# Generated by FakeRAM 2.0
VERSION 5.7 ;
BUSBITCHARS "[]" ;
PROPERTYDEFINITIONS
  MACRO width INTEGER ;
  MACRO depth INTEGER ;
  MACRO banks INTEGER ;
END PROPERTYDEFINITIONS
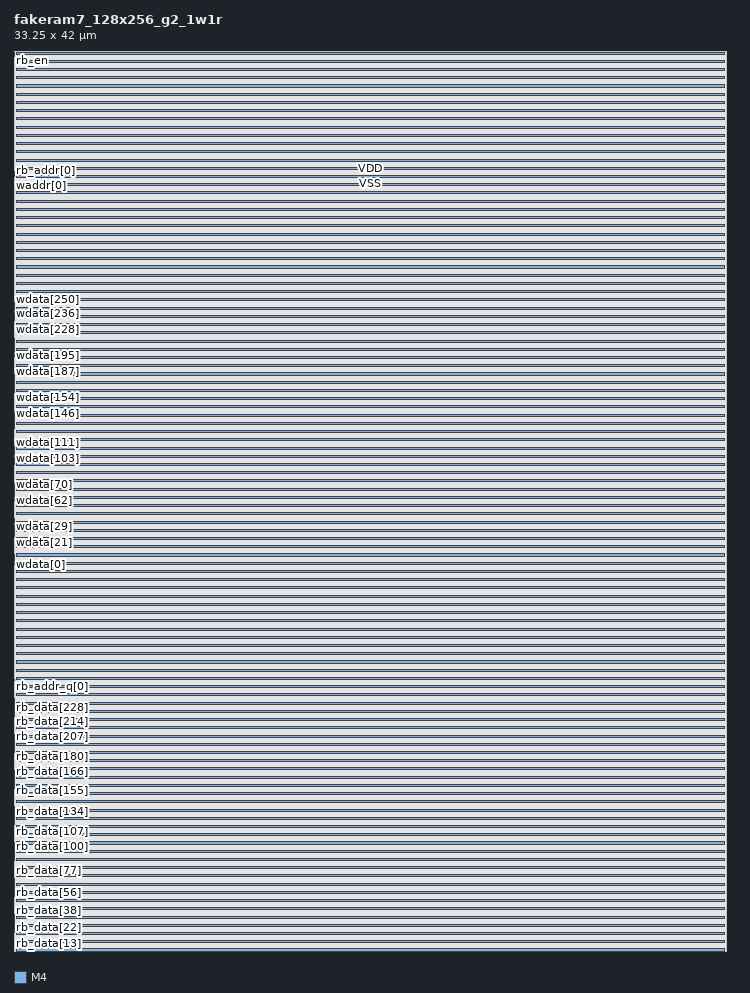
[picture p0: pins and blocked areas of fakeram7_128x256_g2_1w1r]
MACRO fakeram7_128x256_g2_1w1r
  PROPERTY width 256 ;
  PROPERTY depth 128 ;
  PROPERTY banks 1 ;
  FOREIGN fakeram7_128x256_g2_1w1r 0 0 ;
  SYMMETRY X Y R90 ;
  SIZE 33.2500 BY 42.0000 ;
  CLASS BLOCK ;
  PIN wdata[0]
    DIRECTION INPUT ;
    USE SIGNAL ;
    PORT
      LAYER M4 ;
      RECT 0.00000 18.04800 0.03600 18.07200 ;
    END
  END wdata[0]
  PIN wdata[1]
    DIRECTION INPUT ;
    USE SIGNAL ;
    PORT
      LAYER M4 ;
      RECT 0.00000 18.09600 0.03600 18.12000 ;
    END
  END wdata[1]
  PIN wdata[2]
    DIRECTION INPUT ;
    USE SIGNAL ;
    PORT
      LAYER M4 ;
      RECT 0.00000 18.14400 0.03600 18.16800 ;
    END
  END wdata[2]
  PIN wdata[3]
    DIRECTION INPUT ;
    USE SIGNAL ;
    PORT
      LAYER M4 ;
      RECT 0.00000 18.19200 0.03600 18.21600 ;
    END
  END wdata[3]
  PIN wdata[4]
    DIRECTION INPUT ;
    USE SIGNAL ;
    PORT
      LAYER M4 ;
      RECT 0.00000 18.24000 0.03600 18.26400 ;
    END
  END wdata[4]
  PIN wdata[5]
    DIRECTION INPUT ;
    USE SIGNAL ;
    PORT
      LAYER M4 ;
      RECT 0.00000 18.28800 0.03600 18.31200 ;
    END
  END wdata[5]
  PIN wdata[6]
    DIRECTION INPUT ;
    USE SIGNAL ;
    PORT
      LAYER M4 ;
      RECT 0.00000 18.33600 0.03600 18.36000 ;
    END
  END wdata[6]
  PIN wdata[7]
    DIRECTION INPUT ;
    USE SIGNAL ;
    PORT
      LAYER M4 ;
      RECT 0.00000 18.38400 0.03600 18.40800 ;
    END
  END wdata[7]
  PIN wdata[8]
    DIRECTION INPUT ;
    USE SIGNAL ;
    PORT
      LAYER M4 ;
      RECT 0.00000 18.43200 0.03600 18.45600 ;
    END
  END wdata[8]
  PIN wdata[9]
    DIRECTION INPUT ;
    USE SIGNAL ;
    PORT
      LAYER M4 ;
      RECT 0.00000 18.48000 0.03600 18.50400 ;
    END
  END wdata[9]
  PIN wdata[10]
    DIRECTION INPUT ;
    USE SIGNAL ;
    PORT
      LAYER M4 ;
      RECT 0.00000 18.52800 0.03600 18.55200 ;
    END
  END wdata[10]
  PIN wdata[11]
    DIRECTION INPUT ;
    USE SIGNAL ;
    PORT
      LAYER M4 ;
      RECT 0.00000 18.57600 0.03600 18.60000 ;
    END
  END wdata[11]
  PIN wdata[12]
    DIRECTION INPUT ;
    USE SIGNAL ;
    PORT
      LAYER M4 ;
      RECT 0.00000 18.62400 0.03600 18.64800 ;
    END
  END wdata[12]
  PIN wdata[13]
    DIRECTION INPUT ;
    USE SIGNAL ;
    PORT
      LAYER M4 ;
      RECT 0.00000 18.67200 0.03600 18.69600 ;
    END
  END wdata[13]
  PIN wdata[14]
    DIRECTION INPUT ;
    USE SIGNAL ;
    PORT
      LAYER M4 ;
      RECT 0.00000 18.72000 0.03600 18.74400 ;
    END
  END wdata[14]
  PIN wdata[15]
    DIRECTION INPUT ;
    USE SIGNAL ;
    PORT
      LAYER M4 ;
      RECT 0.00000 18.76800 0.03600 18.79200 ;
    END
  END wdata[15]
  PIN wdata[16]
    DIRECTION INPUT ;
    USE SIGNAL ;
    PORT
      LAYER M4 ;
      RECT 0.00000 18.81600 0.03600 18.84000 ;
    END
  END wdata[16]
  PIN wdata[17]
    DIRECTION INPUT ;
    USE SIGNAL ;
    PORT
      LAYER M4 ;
      RECT 0.00000 18.86400 0.03600 18.88800 ;
    END
  END wdata[17]
  PIN wdata[18]
    DIRECTION INPUT ;
    USE SIGNAL ;
    PORT
      LAYER M4 ;
      RECT 0.00000 18.91200 0.03600 18.93600 ;
    END
  END wdata[18]
  PIN wdata[19]
    DIRECTION INPUT ;
    USE SIGNAL ;
    PORT
      LAYER M4 ;
      RECT 0.00000 18.96000 0.03600 18.98400 ;
    END
  END wdata[19]
  PIN wdata[20]
    DIRECTION INPUT ;
    USE SIGNAL ;
    PORT
      LAYER M4 ;
      RECT 0.00000 19.00800 0.03600 19.03200 ;
    END
  END wdata[20]
  PIN wdata[21]
    DIRECTION INPUT ;
    USE SIGNAL ;
    PORT
      LAYER M4 ;
      RECT 0.00000 19.05600 0.03600 19.08000 ;
    END
  END wdata[21]
  PIN wdata[22]
    DIRECTION INPUT ;
    USE SIGNAL ;
    PORT
      LAYER M4 ;
      RECT 0.00000 19.10400 0.03600 19.12800 ;
    END
  END wdata[22]
  PIN wdata[23]
    DIRECTION INPUT ;
    USE SIGNAL ;
    PORT
      LAYER M4 ;
      RECT 0.00000 19.15200 0.03600 19.17600 ;
    END
  END wdata[23]
  PIN wdata[24]
    DIRECTION INPUT ;
    USE SIGNAL ;
    PORT
      LAYER M4 ;
      RECT 0.00000 19.20000 0.03600 19.22400 ;
    END
  END wdata[24]
  PIN wdata[25]
    DIRECTION INPUT ;
    USE SIGNAL ;
    PORT
      LAYER M4 ;
      RECT 0.00000 19.24800 0.03600 19.27200 ;
    END
  END wdata[25]
  PIN wdata[26]
    DIRECTION INPUT ;
    USE SIGNAL ;
    PORT
      LAYER M4 ;
      RECT 0.00000 19.29600 0.03600 19.32000 ;
    END
  END wdata[26]
  PIN wdata[27]
    DIRECTION INPUT ;
    USE SIGNAL ;
    PORT
      LAYER M4 ;
      RECT 0.00000 19.34400 0.03600 19.36800 ;
    END
  END wdata[27]
  PIN wdata[28]
    DIRECTION INPUT ;
    USE SIGNAL ;
    PORT
      LAYER M4 ;
      RECT 0.00000 19.39200 0.03600 19.41600 ;
    END
  END wdata[28]
  PIN wdata[29]
    DIRECTION INPUT ;
    USE SIGNAL ;
    PORT
      LAYER M4 ;
      RECT 0.00000 19.44000 0.03600 19.46400 ;
    END
  END wdata[29]
  PIN wdata[30]
    DIRECTION INPUT ;
    USE SIGNAL ;
    PORT
      LAYER M4 ;
      RECT 0.00000 19.48800 0.03600 19.51200 ;
    END
  END wdata[30]
  PIN wdata[31]
    DIRECTION INPUT ;
    USE SIGNAL ;
    PORT
      LAYER M4 ;
      RECT 0.00000 19.53600 0.03600 19.56000 ;
    END
  END wdata[31]
  PIN wdata[32]
    DIRECTION INPUT ;
    USE SIGNAL ;
    PORT
      LAYER M4 ;
      RECT 0.00000 19.58400 0.03600 19.60800 ;
    END
  END wdata[32]
  PIN wdata[33]
    DIRECTION INPUT ;
    USE SIGNAL ;
    PORT
      LAYER M4 ;
      RECT 0.00000 19.63200 0.03600 19.65600 ;
    END
  END wdata[33]
  PIN wdata[34]
    DIRECTION INPUT ;
    USE SIGNAL ;
    PORT
      LAYER M4 ;
      RECT 0.00000 19.68000 0.03600 19.70400 ;
    END
  END wdata[34]
  PIN wdata[35]
    DIRECTION INPUT ;
    USE SIGNAL ;
    PORT
      LAYER M4 ;
      RECT 0.00000 19.72800 0.03600 19.75200 ;
    END
  END wdata[35]
  PIN wdata[36]
    DIRECTION INPUT ;
    USE SIGNAL ;
    PORT
      LAYER M4 ;
      RECT 0.00000 19.77600 0.03600 19.80000 ;
    END
  END wdata[36]
  PIN wdata[37]
    DIRECTION INPUT ;
    USE SIGNAL ;
    PORT
      LAYER M4 ;
      RECT 0.00000 19.82400 0.03600 19.84800 ;
    END
  END wdata[37]
  PIN wdata[38]
    DIRECTION INPUT ;
    USE SIGNAL ;
    PORT
      LAYER M4 ;
      RECT 0.00000 19.87200 0.03600 19.89600 ;
    END
  END wdata[38]
  PIN wdata[39]
    DIRECTION INPUT ;
    USE SIGNAL ;
    PORT
      LAYER M4 ;
      RECT 0.00000 19.92000 0.03600 19.94400 ;
    END
  END wdata[39]
  PIN wdata[40]
    DIRECTION INPUT ;
    USE SIGNAL ;
    PORT
      LAYER M4 ;
      RECT 0.00000 19.96800 0.03600 19.99200 ;
    END
  END wdata[40]
  PIN wdata[41]
    DIRECTION INPUT ;
    USE SIGNAL ;
    PORT
      LAYER M4 ;
      RECT 0.00000 20.01600 0.03600 20.04000 ;
    END
  END wdata[41]
  PIN wdata[42]
    DIRECTION INPUT ;
    USE SIGNAL ;
    PORT
      LAYER M4 ;
      RECT 0.00000 20.06400 0.03600 20.08800 ;
    END
  END wdata[42]
  PIN wdata[43]
    DIRECTION INPUT ;
    USE SIGNAL ;
    PORT
      LAYER M4 ;
      RECT 0.00000 20.11200 0.03600 20.13600 ;
    END
  END wdata[43]
  PIN wdata[44]
    DIRECTION INPUT ;
    USE SIGNAL ;
    PORT
      LAYER M4 ;
      RECT 0.00000 20.16000 0.03600 20.18400 ;
    END
  END wdata[44]
  PIN wdata[45]
    DIRECTION INPUT ;
    USE SIGNAL ;
    PORT
      LAYER M4 ;
      RECT 0.00000 20.20800 0.03600 20.23200 ;
    END
  END wdata[45]
  PIN wdata[46]
    DIRECTION INPUT ;
    USE SIGNAL ;
    PORT
      LAYER M4 ;
      RECT 0.00000 20.25600 0.03600 20.28000 ;
    END
  END wdata[46]
  PIN wdata[47]
    DIRECTION INPUT ;
    USE SIGNAL ;
    PORT
      LAYER M4 ;
      RECT 0.00000 20.30400 0.03600 20.32800 ;
    END
  END wdata[47]
  PIN wdata[48]
    DIRECTION INPUT ;
    USE SIGNAL ;
    PORT
      LAYER M4 ;
      RECT 0.00000 20.35200 0.03600 20.37600 ;
    END
  END wdata[48]
  PIN wdata[49]
    DIRECTION INPUT ;
    USE SIGNAL ;
    PORT
      LAYER M4 ;
      RECT 0.00000 20.40000 0.03600 20.42400 ;
    END
  END wdata[49]
  PIN wdata[50]
    DIRECTION INPUT ;
    USE SIGNAL ;
    PORT
      LAYER M4 ;
      RECT 0.00000 20.44800 0.03600 20.47200 ;
    END
  END wdata[50]
  PIN wdata[51]
    DIRECTION INPUT ;
    USE SIGNAL ;
    PORT
      LAYER M4 ;
      RECT 0.00000 20.49600 0.03600 20.52000 ;
    END
  END wdata[51]
  PIN wdata[52]
    DIRECTION INPUT ;
    USE SIGNAL ;
    PORT
      LAYER M4 ;
      RECT 0.00000 20.54400 0.03600 20.56800 ;
    END
  END wdata[52]
  PIN wdata[53]
    DIRECTION INPUT ;
    USE SIGNAL ;
    PORT
      LAYER M4 ;
      RECT 0.00000 20.59200 0.03600 20.61600 ;
    END
  END wdata[53]
  PIN wdata[54]
    DIRECTION INPUT ;
    USE SIGNAL ;
    PORT
      LAYER M4 ;
      RECT 0.00000 20.64000 0.03600 20.66400 ;
    END
  END wdata[54]
  PIN wdata[55]
    DIRECTION INPUT ;
    USE SIGNAL ;
    PORT
      LAYER M4 ;
      RECT 0.00000 20.68800 0.03600 20.71200 ;
    END
  END wdata[55]
  PIN wdata[56]
    DIRECTION INPUT ;
    USE SIGNAL ;
    PORT
      LAYER M4 ;
      RECT 0.00000 20.73600 0.03600 20.76000 ;
    END
  END wdata[56]
  PIN wdata[57]
    DIRECTION INPUT ;
    USE SIGNAL ;
    PORT
      LAYER M4 ;
      RECT 0.00000 20.78400 0.03600 20.80800 ;
    END
  END wdata[57]
  PIN wdata[58]
    DIRECTION INPUT ;
    USE SIGNAL ;
    PORT
      LAYER M4 ;
      RECT 0.00000 20.83200 0.03600 20.85600 ;
    END
  END wdata[58]
  PIN wdata[59]
    DIRECTION INPUT ;
    USE SIGNAL ;
    PORT
      LAYER M4 ;
      RECT 0.00000 20.88000 0.03600 20.90400 ;
    END
  END wdata[59]
  PIN wdata[60]
    DIRECTION INPUT ;
    USE SIGNAL ;
    PORT
      LAYER M4 ;
      RECT 0.00000 20.92800 0.03600 20.95200 ;
    END
  END wdata[60]
  PIN wdata[61]
    DIRECTION INPUT ;
    USE SIGNAL ;
    PORT
      LAYER M4 ;
      RECT 0.00000 20.97600 0.03600 21.00000 ;
    END
  END wdata[61]
  PIN wdata[62]
    DIRECTION INPUT ;
    USE SIGNAL ;
    PORT
      LAYER M4 ;
      RECT 0.00000 21.02400 0.03600 21.04800 ;
    END
  END wdata[62]
  PIN wdata[63]
    DIRECTION INPUT ;
    USE SIGNAL ;
    PORT
      LAYER M4 ;
      RECT 0.00000 21.07200 0.03600 21.09600 ;
    END
  END wdata[63]
  PIN wdata[64]
    DIRECTION INPUT ;
    USE SIGNAL ;
    PORT
      LAYER M4 ;
      RECT 0.00000 21.12000 0.03600 21.14400 ;
    END
  END wdata[64]
  PIN wdata[65]
    DIRECTION INPUT ;
    USE SIGNAL ;
    PORT
      LAYER M4 ;
      RECT 0.00000 21.16800 0.03600 21.19200 ;
    END
  END wdata[65]
  PIN wdata[66]
    DIRECTION INPUT ;
    USE SIGNAL ;
    PORT
      LAYER M4 ;
      RECT 0.00000 21.21600 0.03600 21.24000 ;
    END
  END wdata[66]
  PIN wdata[67]
    DIRECTION INPUT ;
    USE SIGNAL ;
    PORT
      LAYER M4 ;
      RECT 0.00000 21.26400 0.03600 21.28800 ;
    END
  END wdata[67]
  PIN wdata[68]
    DIRECTION INPUT ;
    USE SIGNAL ;
    PORT
      LAYER M4 ;
      RECT 0.00000 21.31200 0.03600 21.33600 ;
    END
  END wdata[68]
  PIN wdata[69]
    DIRECTION INPUT ;
    USE SIGNAL ;
    PORT
      LAYER M4 ;
      RECT 0.00000 21.36000 0.03600 21.38400 ;
    END
  END wdata[69]
  PIN wdata[70]
    DIRECTION INPUT ;
    USE SIGNAL ;
    PORT
      LAYER M4 ;
      RECT 0.00000 21.40800 0.03600 21.43200 ;
    END
  END wdata[70]
  PIN wdata[71]
    DIRECTION INPUT ;
    USE SIGNAL ;
    PORT
      LAYER M4 ;
      RECT 0.00000 21.45600 0.03600 21.48000 ;
    END
  END wdata[71]
  PIN wdata[72]
    DIRECTION INPUT ;
    USE SIGNAL ;
    PORT
      LAYER M4 ;
      RECT 0.00000 21.50400 0.03600 21.52800 ;
    END
  END wdata[72]
  PIN wdata[73]
    DIRECTION INPUT ;
    USE SIGNAL ;
    PORT
      LAYER M4 ;
      RECT 0.00000 21.55200 0.03600 21.57600 ;
    END
  END wdata[73]
  PIN wdata[74]
    DIRECTION INPUT ;
    USE SIGNAL ;
    PORT
      LAYER M4 ;
      RECT 0.00000 21.60000 0.03600 21.62400 ;
    END
  END wdata[74]
  PIN wdata[75]
    DIRECTION INPUT ;
    USE SIGNAL ;
    PORT
      LAYER M4 ;
      RECT 0.00000 21.64800 0.03600 21.67200 ;
    END
  END wdata[75]
  PIN wdata[76]
    DIRECTION INPUT ;
    USE SIGNAL ;
    PORT
      LAYER M4 ;
      RECT 0.00000 21.69600 0.03600 21.72000 ;
    END
  END wdata[76]
  PIN wdata[77]
    DIRECTION INPUT ;
    USE SIGNAL ;
    PORT
      LAYER M4 ;
      RECT 0.00000 21.74400 0.03600 21.76800 ;
    END
  END wdata[77]
  PIN wdata[78]
    DIRECTION INPUT ;
    USE SIGNAL ;
    PORT
      LAYER M4 ;
      RECT 0.00000 21.79200 0.03600 21.81600 ;
    END
  END wdata[78]
  PIN wdata[79]
    DIRECTION INPUT ;
    USE SIGNAL ;
    PORT
      LAYER M4 ;
      RECT 0.00000 21.84000 0.03600 21.86400 ;
    END
  END wdata[79]
  PIN wdata[80]
    DIRECTION INPUT ;
    USE SIGNAL ;
    PORT
      LAYER M4 ;
      RECT 0.00000 21.88800 0.03600 21.91200 ;
    END
  END wdata[80]
  PIN wdata[81]
    DIRECTION INPUT ;
    USE SIGNAL ;
    PORT
      LAYER M4 ;
      RECT 0.00000 21.93600 0.03600 21.96000 ;
    END
  END wdata[81]
  PIN wdata[82]
    DIRECTION INPUT ;
    USE SIGNAL ;
    PORT
      LAYER M4 ;
      RECT 0.00000 21.98400 0.03600 22.00800 ;
    END
  END wdata[82]
  PIN wdata[83]
    DIRECTION INPUT ;
    USE SIGNAL ;
    PORT
      LAYER M4 ;
      RECT 0.00000 22.03200 0.03600 22.05600 ;
    END
  END wdata[83]
  PIN wdata[84]
    DIRECTION INPUT ;
    USE SIGNAL ;
    PORT
      LAYER M4 ;
      RECT 0.00000 22.08000 0.03600 22.10400 ;
    END
  END wdata[84]
  PIN wdata[85]
    DIRECTION INPUT ;
    USE SIGNAL ;
    PORT
      LAYER M4 ;
      RECT 0.00000 22.12800 0.03600 22.15200 ;
    END
  END wdata[85]
  PIN wdata[86]
    DIRECTION INPUT ;
    USE SIGNAL ;
    PORT
      LAYER M4 ;
      RECT 0.00000 22.17600 0.03600 22.20000 ;
    END
  END wdata[86]
  PIN wdata[87]
    DIRECTION INPUT ;
    USE SIGNAL ;
    PORT
      LAYER M4 ;
      RECT 0.00000 22.22400 0.03600 22.24800 ;
    END
  END wdata[87]
  PIN wdata[88]
    DIRECTION INPUT ;
    USE SIGNAL ;
    PORT
      LAYER M4 ;
      RECT 0.00000 22.27200 0.03600 22.29600 ;
    END
  END wdata[88]
  PIN wdata[89]
    DIRECTION INPUT ;
    USE SIGNAL ;
    PORT
      LAYER M4 ;
      RECT 0.00000 22.32000 0.03600 22.34400 ;
    END
  END wdata[89]
  PIN wdata[90]
    DIRECTION INPUT ;
    USE SIGNAL ;
    PORT
      LAYER M4 ;
      RECT 0.00000 22.36800 0.03600 22.39200 ;
    END
  END wdata[90]
  PIN wdata[91]
    DIRECTION INPUT ;
    USE SIGNAL ;
    PORT
      LAYER M4 ;
      RECT 0.00000 22.41600 0.03600 22.44000 ;
    END
  END wdata[91]
  PIN wdata[92]
    DIRECTION INPUT ;
    USE SIGNAL ;
    PORT
      LAYER M4 ;
      RECT 0.00000 22.46400 0.03600 22.48800 ;
    END
  END wdata[92]
  PIN wdata[93]
    DIRECTION INPUT ;
    USE SIGNAL ;
    PORT
      LAYER M4 ;
      RECT 0.00000 22.51200 0.03600 22.53600 ;
    END
  END wdata[93]
  PIN wdata[94]
    DIRECTION INPUT ;
    USE SIGNAL ;
    PORT
      LAYER M4 ;
      RECT 0.00000 22.56000 0.03600 22.58400 ;
    END
  END wdata[94]
  PIN wdata[95]
    DIRECTION INPUT ;
    USE SIGNAL ;
    PORT
      LAYER M4 ;
      RECT 0.00000 22.60800 0.03600 22.63200 ;
    END
  END wdata[95]
  PIN wdata[96]
    DIRECTION INPUT ;
    USE SIGNAL ;
    PORT
      LAYER M4 ;
      RECT 0.00000 22.65600 0.03600 22.68000 ;
    END
  END wdata[96]
  PIN wdata[97]
    DIRECTION INPUT ;
    USE SIGNAL ;
    PORT
      LAYER M4 ;
      RECT 0.00000 22.70400 0.03600 22.72800 ;
    END
  END wdata[97]
  PIN wdata[98]
    DIRECTION INPUT ;
    USE SIGNAL ;
    PORT
      LAYER M4 ;
      RECT 0.00000 22.75200 0.03600 22.77600 ;
    END
  END wdata[98]
  PIN wdata[99]
    DIRECTION INPUT ;
    USE SIGNAL ;
    PORT
      LAYER M4 ;
      RECT 0.00000 22.80000 0.03600 22.82400 ;
    END
  END wdata[99]
  PIN wdata[100]
    DIRECTION INPUT ;
    USE SIGNAL ;
    PORT
      LAYER M4 ;
      RECT 0.00000 22.84800 0.03600 22.87200 ;
    END
  END wdata[100]
  PIN wdata[101]
    DIRECTION INPUT ;
    USE SIGNAL ;
    PORT
      LAYER M4 ;
      RECT 0.00000 22.89600 0.03600 22.92000 ;
    END
  END wdata[101]
  PIN wdata[102]
    DIRECTION INPUT ;
    USE SIGNAL ;
    PORT
      LAYER M4 ;
      RECT 0.00000 22.94400 0.03600 22.96800 ;
    END
  END wdata[102]
  PIN wdata[103]
    DIRECTION INPUT ;
    USE SIGNAL ;
    PORT
      LAYER M4 ;
      RECT 0.00000 22.99200 0.03600 23.01600 ;
    END
  END wdata[103]
  PIN wdata[104]
    DIRECTION INPUT ;
    USE SIGNAL ;
    PORT
      LAYER M4 ;
      RECT 0.00000 23.04000 0.03600 23.06400 ;
    END
  END wdata[104]
  PIN wdata[105]
    DIRECTION INPUT ;
    USE SIGNAL ;
    PORT
      LAYER M4 ;
      RECT 0.00000 23.08800 0.03600 23.11200 ;
    END
  END wdata[105]
  PIN wdata[106]
    DIRECTION INPUT ;
    USE SIGNAL ;
    PORT
      LAYER M4 ;
      RECT 0.00000 23.13600 0.03600 23.16000 ;
    END
  END wdata[106]
  PIN wdata[107]
    DIRECTION INPUT ;
    USE SIGNAL ;
    PORT
      LAYER M4 ;
      RECT 0.00000 23.18400 0.03600 23.20800 ;
    END
  END wdata[107]
  PIN wdata[108]
    DIRECTION INPUT ;
    USE SIGNAL ;
    PORT
      LAYER M4 ;
      RECT 0.00000 23.23200 0.03600 23.25600 ;
    END
  END wdata[108]
  PIN wdata[109]
    DIRECTION INPUT ;
    USE SIGNAL ;
    PORT
      LAYER M4 ;
      RECT 0.00000 23.28000 0.03600 23.30400 ;
    END
  END wdata[109]
  PIN wdata[110]
    DIRECTION INPUT ;
    USE SIGNAL ;
    PORT
      LAYER M4 ;
      RECT 0.00000 23.32800 0.03600 23.35200 ;
    END
  END wdata[110]
  PIN wdata[111]
    DIRECTION INPUT ;
    USE SIGNAL ;
    PORT
      LAYER M4 ;
      RECT 0.00000 23.37600 0.03600 23.40000 ;
    END
  END wdata[111]
  PIN wdata[112]
    DIRECTION INPUT ;
    USE SIGNAL ;
    PORT
      LAYER M4 ;
      RECT 0.00000 23.42400 0.03600 23.44800 ;
    END
  END wdata[112]
  PIN wdata[113]
    DIRECTION INPUT ;
    USE SIGNAL ;
    PORT
      LAYER M4 ;
      RECT 0.00000 23.47200 0.03600 23.49600 ;
    END
  END wdata[113]
  PIN wdata[114]
    DIRECTION INPUT ;
    USE SIGNAL ;
    PORT
      LAYER M4 ;
      RECT 0.00000 23.52000 0.03600 23.54400 ;
    END
  END wdata[114]
  PIN wdata[115]
    DIRECTION INPUT ;
    USE SIGNAL ;
    PORT
      LAYER M4 ;
      RECT 0.00000 23.56800 0.03600 23.59200 ;
    END
  END wdata[115]
  PIN wdata[116]
    DIRECTION INPUT ;
    USE SIGNAL ;
    PORT
      LAYER M4 ;
      RECT 0.00000 23.61600 0.03600 23.64000 ;
    END
  END wdata[116]
  PIN wdata[117]
    DIRECTION INPUT ;
    USE SIGNAL ;
    PORT
      LAYER M4 ;
      RECT 0.00000 23.66400 0.03600 23.68800 ;
    END
  END wdata[117]
  PIN wdata[118]
    DIRECTION INPUT ;
    USE SIGNAL ;
    PORT
      LAYER M4 ;
      RECT 0.00000 23.71200 0.03600 23.73600 ;
    END
  END wdata[118]
  PIN wdata[119]
    DIRECTION INPUT ;
    USE SIGNAL ;
    PORT
      LAYER M4 ;
      RECT 0.00000 23.76000 0.03600 23.78400 ;
    END
  END wdata[119]
  PIN wdata[120]
    DIRECTION INPUT ;
    USE SIGNAL ;
    PORT
      LAYER M4 ;
      RECT 0.00000 23.80800 0.03600 23.83200 ;
    END
  END wdata[120]
  PIN wdata[121]
    DIRECTION INPUT ;
    USE SIGNAL ;
    PORT
      LAYER M4 ;
      RECT 0.00000 23.85600 0.03600 23.88000 ;
    END
  END wdata[121]
  PIN wdata[122]
    DIRECTION INPUT ;
    USE SIGNAL ;
    PORT
      LAYER M4 ;
      RECT 0.00000 23.90400 0.03600 23.92800 ;
    END
  END wdata[122]
  PIN wdata[123]
    DIRECTION INPUT ;
    USE SIGNAL ;
    PORT
      LAYER M4 ;
      RECT 0.00000 23.95200 0.03600 23.97600 ;
    END
  END wdata[123]
  PIN wdata[124]
    DIRECTION INPUT ;
    USE SIGNAL ;
    PORT
      LAYER M4 ;
      RECT 0.00000 24.00000 0.03600 24.02400 ;
    END
  END wdata[124]
  PIN wdata[125]
    DIRECTION INPUT ;
    USE SIGNAL ;
    PORT
      LAYER M4 ;
      RECT 0.00000 24.04800 0.03600 24.07200 ;
    END
  END wdata[125]
  PIN wdata[126]
    DIRECTION INPUT ;
    USE SIGNAL ;
    PORT
      LAYER M4 ;
      RECT 0.00000 24.09600 0.03600 24.12000 ;
    END
  END wdata[126]
  PIN wdata[127]
    DIRECTION INPUT ;
    USE SIGNAL ;
    PORT
      LAYER M4 ;
      RECT 0.00000 24.14400 0.03600 24.16800 ;
    END
  END wdata[127]
  PIN wdata[128]
    DIRECTION INPUT ;
    USE SIGNAL ;
    PORT
      LAYER M4 ;
      RECT 0.00000 24.19200 0.03600 24.21600 ;
    END
  END wdata[128]
  PIN wdata[129]
    DIRECTION INPUT ;
    USE SIGNAL ;
    PORT
      LAYER M4 ;
      RECT 0.00000 24.24000 0.03600 24.26400 ;
    END
  END wdata[129]
  PIN wdata[130]
    DIRECTION INPUT ;
    USE SIGNAL ;
    PORT
      LAYER M4 ;
      RECT 0.00000 24.28800 0.03600 24.31200 ;
    END
  END wdata[130]
  PIN wdata[131]
    DIRECTION INPUT ;
    USE SIGNAL ;
    PORT
      LAYER M4 ;
      RECT 0.00000 24.33600 0.03600 24.36000 ;
    END
  END wdata[131]
  PIN wdata[132]
    DIRECTION INPUT ;
    USE SIGNAL ;
    PORT
      LAYER M4 ;
      RECT 0.00000 24.38400 0.03600 24.40800 ;
    END
  END wdata[132]
  PIN wdata[133]
    DIRECTION INPUT ;
    USE SIGNAL ;
    PORT
      LAYER M4 ;
      RECT 0.00000 24.43200 0.03600 24.45600 ;
    END
  END wdata[133]
  PIN wdata[134]
    DIRECTION INPUT ;
    USE SIGNAL ;
    PORT
      LAYER M4 ;
      RECT 0.00000 24.48000 0.03600 24.50400 ;
    END
  END wdata[134]
  PIN wdata[135]
    DIRECTION INPUT ;
    USE SIGNAL ;
    PORT
      LAYER M4 ;
      RECT 0.00000 24.52800 0.03600 24.55200 ;
    END
  END wdata[135]
  PIN wdata[136]
    DIRECTION INPUT ;
    USE SIGNAL ;
    PORT
      LAYER M4 ;
      RECT 0.00000 24.57600 0.03600 24.60000 ;
    END
  END wdata[136]
  PIN wdata[137]
    DIRECTION INPUT ;
    USE SIGNAL ;
    PORT
      LAYER M4 ;
      RECT 0.00000 24.62400 0.03600 24.64800 ;
    END
  END wdata[137]
  PIN wdata[138]
    DIRECTION INPUT ;
    USE SIGNAL ;
    PORT
      LAYER M4 ;
      RECT 0.00000 24.67200 0.03600 24.69600 ;
    END
  END wdata[138]
  PIN wdata[139]
    DIRECTION INPUT ;
    USE SIGNAL ;
    PORT
      LAYER M4 ;
      RECT 0.00000 24.72000 0.03600 24.74400 ;
    END
  END wdata[139]
  PIN wdata[140]
    DIRECTION INPUT ;
    USE SIGNAL ;
    PORT
      LAYER M4 ;
      RECT 0.00000 24.76800 0.03600 24.79200 ;
    END
  END wdata[140]
  PIN wdata[141]
    DIRECTION INPUT ;
    USE SIGNAL ;
    PORT
      LAYER M4 ;
      RECT 0.00000 24.81600 0.03600 24.84000 ;
    END
  END wdata[141]
  PIN wdata[142]
    DIRECTION INPUT ;
    USE SIGNAL ;
    PORT
      LAYER M4 ;
      RECT 0.00000 24.86400 0.03600 24.88800 ;
    END
  END wdata[142]
  PIN wdata[143]
    DIRECTION INPUT ;
    USE SIGNAL ;
    PORT
      LAYER M4 ;
      RECT 0.00000 24.91200 0.03600 24.93600 ;
    END
  END wdata[143]
  PIN wdata[144]
    DIRECTION INPUT ;
    USE SIGNAL ;
    PORT
      LAYER M4 ;
      RECT 0.00000 24.96000 0.03600 24.98400 ;
    END
  END wdata[144]
  PIN wdata[145]
    DIRECTION INPUT ;
    USE SIGNAL ;
    PORT
      LAYER M4 ;
      RECT 0.00000 25.00800 0.03600 25.03200 ;
    END
  END wdata[145]
  PIN wdata[146]
    DIRECTION INPUT ;
    USE SIGNAL ;
    PORT
      LAYER M4 ;
      RECT 0.00000 25.05600 0.03600 25.08000 ;
    END
  END wdata[146]
  PIN wdata[147]
    DIRECTION INPUT ;
    USE SIGNAL ;
    PORT
      LAYER M4 ;
      RECT 0.00000 25.10400 0.03600 25.12800 ;
    END
  END wdata[147]
  PIN wdata[148]
    DIRECTION INPUT ;
    USE SIGNAL ;
    PORT
      LAYER M4 ;
      RECT 0.00000 25.15200 0.03600 25.17600 ;
    END
  END wdata[148]
  PIN wdata[149]
    DIRECTION INPUT ;
    USE SIGNAL ;
    PORT
      LAYER M4 ;
      RECT 0.00000 25.20000 0.03600 25.22400 ;
    END
  END wdata[149]
  PIN wdata[150]
    DIRECTION INPUT ;
    USE SIGNAL ;
    PORT
      LAYER M4 ;
      RECT 0.00000 25.24800 0.03600 25.27200 ;
    END
  END wdata[150]
  PIN wdata[151]
    DIRECTION INPUT ;
    USE SIGNAL ;
    PORT
      LAYER M4 ;
      RECT 0.00000 25.29600 0.03600 25.32000 ;
    END
  END wdata[151]
  PIN wdata[152]
    DIRECTION INPUT ;
    USE SIGNAL ;
    PORT
      LAYER M4 ;
      RECT 0.00000 25.34400 0.03600 25.36800 ;
    END
  END wdata[152]
  PIN wdata[153]
    DIRECTION INPUT ;
    USE SIGNAL ;
    PORT
      LAYER M4 ;
      RECT 0.00000 25.39200 0.03600 25.41600 ;
    END
  END wdata[153]
  PIN wdata[154]
    DIRECTION INPUT ;
    USE SIGNAL ;
    PORT
      LAYER M4 ;
      RECT 0.00000 25.44000 0.03600 25.46400 ;
    END
  END wdata[154]
  PIN wdata[155]
    DIRECTION INPUT ;
    USE SIGNAL ;
    PORT
      LAYER M4 ;
      RECT 0.00000 25.48800 0.03600 25.51200 ;
    END
  END wdata[155]
  PIN wdata[156]
    DIRECTION INPUT ;
    USE SIGNAL ;
    PORT
      LAYER M4 ;
      RECT 0.00000 25.53600 0.03600 25.56000 ;
    END
  END wdata[156]
  PIN wdata[157]
    DIRECTION INPUT ;
    USE SIGNAL ;
    PORT
      LAYER M4 ;
      RECT 0.00000 25.58400 0.03600 25.60800 ;
    END
  END wdata[157]
  PIN wdata[158]
    DIRECTION INPUT ;
    USE SIGNAL ;
    PORT
      LAYER M4 ;
      RECT 0.00000 25.63200 0.03600 25.65600 ;
    END
  END wdata[158]
  PIN wdata[159]
    DIRECTION INPUT ;
    USE SIGNAL ;
    PORT
      LAYER M4 ;
      RECT 0.00000 25.68000 0.03600 25.70400 ;
    END
  END wdata[159]
  PIN wdata[160]
    DIRECTION INPUT ;
    USE SIGNAL ;
    PORT
      LAYER M4 ;
      RECT 0.00000 25.72800 0.03600 25.75200 ;
    END
  END wdata[160]
  PIN wdata[161]
    DIRECTION INPUT ;
    USE SIGNAL ;
    PORT
      LAYER M4 ;
      RECT 0.00000 25.77600 0.03600 25.80000 ;
    END
  END wdata[161]
  PIN wdata[162]
    DIRECTION INPUT ;
    USE SIGNAL ;
    PORT
      LAYER M4 ;
      RECT 0.00000 25.82400 0.03600 25.84800 ;
    END
  END wdata[162]
  PIN wdata[163]
    DIRECTION INPUT ;
    USE SIGNAL ;
    PORT
      LAYER M4 ;
      RECT 0.00000 25.87200 0.03600 25.89600 ;
    END
  END wdata[163]
  PIN wdata[164]
    DIRECTION INPUT ;
    USE SIGNAL ;
    PORT
      LAYER M4 ;
      RECT 0.00000 25.92000 0.03600 25.94400 ;
    END
  END wdata[164]
  PIN wdata[165]
    DIRECTION INPUT ;
    USE SIGNAL ;
    PORT
      LAYER M4 ;
      RECT 0.00000 25.96800 0.03600 25.99200 ;
    END
  END wdata[165]
  PIN wdata[166]
    DIRECTION INPUT ;
    USE SIGNAL ;
    PORT
      LAYER M4 ;
      RECT 0.00000 26.01600 0.03600 26.04000 ;
    END
  END wdata[166]
  PIN wdata[167]
    DIRECTION INPUT ;
    USE SIGNAL ;
    PORT
      LAYER M4 ;
      RECT 0.00000 26.06400 0.03600 26.08800 ;
    END
  END wdata[167]
  PIN wdata[168]
    DIRECTION INPUT ;
    USE SIGNAL ;
    PORT
      LAYER M4 ;
      RECT 0.00000 26.11200 0.03600 26.13600 ;
    END
  END wdata[168]
  PIN wdata[169]
    DIRECTION INPUT ;
    USE SIGNAL ;
    PORT
      LAYER M4 ;
      RECT 0.00000 26.16000 0.03600 26.18400 ;
    END
  END wdata[169]
  PIN wdata[170]
    DIRECTION INPUT ;
    USE SIGNAL ;
    PORT
      LAYER M4 ;
      RECT 0.00000 26.20800 0.03600 26.23200 ;
    END
  END wdata[170]
  PIN wdata[171]
    DIRECTION INPUT ;
    USE SIGNAL ;
    PORT
      LAYER M4 ;
      RECT 0.00000 26.25600 0.03600 26.28000 ;
    END
  END wdata[171]
  PIN wdata[172]
    DIRECTION INPUT ;
    USE SIGNAL ;
    PORT
      LAYER M4 ;
      RECT 0.00000 26.30400 0.03600 26.32800 ;
    END
  END wdata[172]
  PIN wdata[173]
    DIRECTION INPUT ;
    USE SIGNAL ;
    PORT
      LAYER M4 ;
      RECT 0.00000 26.35200 0.03600 26.37600 ;
    END
  END wdata[173]
  PIN wdata[174]
    DIRECTION INPUT ;
    USE SIGNAL ;
    PORT
      LAYER M4 ;
      RECT 0.00000 26.40000 0.03600 26.42400 ;
    END
  END wdata[174]
  PIN wdata[175]
    DIRECTION INPUT ;
    USE SIGNAL ;
    PORT
      LAYER M4 ;
      RECT 0.00000 26.44800 0.03600 26.47200 ;
    END
  END wdata[175]
  PIN wdata[176]
    DIRECTION INPUT ;
    USE SIGNAL ;
    PORT
      LAYER M4 ;
      RECT 0.00000 26.49600 0.03600 26.52000 ;
    END
  END wdata[176]
  PIN wdata[177]
    DIRECTION INPUT ;
    USE SIGNAL ;
    PORT
      LAYER M4 ;
      RECT 0.00000 26.54400 0.03600 26.56800 ;
    END
  END wdata[177]
  PIN wdata[178]
    DIRECTION INPUT ;
    USE SIGNAL ;
    PORT
      LAYER M4 ;
      RECT 0.00000 26.59200 0.03600 26.61600 ;
    END
  END wdata[178]
  PIN wdata[179]
    DIRECTION INPUT ;
    USE SIGNAL ;
    PORT
      LAYER M4 ;
      RECT 0.00000 26.64000 0.03600 26.66400 ;
    END
  END wdata[179]
  PIN wdata[180]
    DIRECTION INPUT ;
    USE SIGNAL ;
    PORT
      LAYER M4 ;
      RECT 0.00000 26.68800 0.03600 26.71200 ;
    END
  END wdata[180]
  PIN wdata[181]
    DIRECTION INPUT ;
    USE SIGNAL ;
    PORT
      LAYER M4 ;
      RECT 0.00000 26.73600 0.03600 26.76000 ;
    END
  END wdata[181]
  PIN wdata[182]
    DIRECTION INPUT ;
    USE SIGNAL ;
    PORT
      LAYER M4 ;
      RECT 0.00000 26.78400 0.03600 26.80800 ;
    END
  END wdata[182]
  PIN wdata[183]
    DIRECTION INPUT ;
    USE SIGNAL ;
    PORT
      LAYER M4 ;
      RECT 0.00000 26.83200 0.03600 26.85600 ;
    END
  END wdata[183]
  PIN wdata[184]
    DIRECTION INPUT ;
    USE SIGNAL ;
    PORT
      LAYER M4 ;
      RECT 0.00000 26.88000 0.03600 26.90400 ;
    END
  END wdata[184]
  PIN wdata[185]
    DIRECTION INPUT ;
    USE SIGNAL ;
    PORT
      LAYER M4 ;
      RECT 0.00000 26.92800 0.03600 26.95200 ;
    END
  END wdata[185]
  PIN wdata[186]
    DIRECTION INPUT ;
    USE SIGNAL ;
    PORT
      LAYER M4 ;
      RECT 0.00000 26.97600 0.03600 27.00000 ;
    END
  END wdata[186]
  PIN wdata[187]
    DIRECTION INPUT ;
    USE SIGNAL ;
    PORT
      LAYER M4 ;
      RECT 0.00000 27.02400 0.03600 27.04800 ;
    END
  END wdata[187]
  PIN wdata[188]
    DIRECTION INPUT ;
    USE SIGNAL ;
    PORT
      LAYER M4 ;
      RECT 0.00000 27.07200 0.03600 27.09600 ;
    END
  END wdata[188]
  PIN wdata[189]
    DIRECTION INPUT ;
    USE SIGNAL ;
    PORT
      LAYER M4 ;
      RECT 0.00000 27.12000 0.03600 27.14400 ;
    END
  END wdata[189]
  PIN wdata[190]
    DIRECTION INPUT ;
    USE SIGNAL ;
    PORT
      LAYER M4 ;
      RECT 0.00000 27.16800 0.03600 27.19200 ;
    END
  END wdata[190]
  PIN wdata[191]
    DIRECTION INPUT ;
    USE SIGNAL ;
    PORT
      LAYER M4 ;
      RECT 0.00000 27.21600 0.03600 27.24000 ;
    END
  END wdata[191]
  PIN wdata[192]
    DIRECTION INPUT ;
    USE SIGNAL ;
    PORT
      LAYER M4 ;
      RECT 0.00000 27.26400 0.03600 27.28800 ;
    END
  END wdata[192]
  PIN wdata[193]
    DIRECTION INPUT ;
    USE SIGNAL ;
    PORT
      LAYER M4 ;
      RECT 0.00000 27.31200 0.03600 27.33600 ;
    END
  END wdata[193]
  PIN wdata[194]
    DIRECTION INPUT ;
    USE SIGNAL ;
    PORT
      LAYER M4 ;
      RECT 0.00000 27.36000 0.03600 27.38400 ;
    END
  END wdata[194]
  PIN wdata[195]
    DIRECTION INPUT ;
    USE SIGNAL ;
    PORT
      LAYER M4 ;
      RECT 0.00000 27.40800 0.03600 27.43200 ;
    END
  END wdata[195]
  PIN wdata[196]
    DIRECTION INPUT ;
    USE SIGNAL ;
    PORT
      LAYER M4 ;
      RECT 0.00000 27.45600 0.03600 27.48000 ;
    END
  END wdata[196]
  PIN wdata[197]
    DIRECTION INPUT ;
    USE SIGNAL ;
    PORT
      LAYER M4 ;
      RECT 0.00000 27.50400 0.03600 27.52800 ;
    END
  END wdata[197]
  PIN wdata[198]
    DIRECTION INPUT ;
    USE SIGNAL ;
    PORT
      LAYER M4 ;
      RECT 0.00000 27.55200 0.03600 27.57600 ;
    END
  END wdata[198]
  PIN wdata[199]
    DIRECTION INPUT ;
    USE SIGNAL ;
    PORT
      LAYER M4 ;
      RECT 0.00000 27.60000 0.03600 27.62400 ;
    END
  END wdata[199]
  PIN wdata[200]
    DIRECTION INPUT ;
    USE SIGNAL ;
    PORT
      LAYER M4 ;
      RECT 0.00000 27.64800 0.03600 27.67200 ;
    END
  END wdata[200]
  PIN wdata[201]
    DIRECTION INPUT ;
    USE SIGNAL ;
    PORT
      LAYER M4 ;
      RECT 0.00000 27.69600 0.03600 27.72000 ;
    END
  END wdata[201]
  PIN wdata[202]
    DIRECTION INPUT ;
    USE SIGNAL ;
    PORT
      LAYER M4 ;
      RECT 0.00000 27.74400 0.03600 27.76800 ;
    END
  END wdata[202]
  PIN wdata[203]
    DIRECTION INPUT ;
    USE SIGNAL ;
    PORT
      LAYER M4 ;
      RECT 0.00000 27.79200 0.03600 27.81600 ;
    END
  END wdata[203]
  PIN wdata[204]
    DIRECTION INPUT ;
    USE SIGNAL ;
    PORT
      LAYER M4 ;
      RECT 0.00000 27.84000 0.03600 27.86400 ;
    END
  END wdata[204]
  PIN wdata[205]
    DIRECTION INPUT ;
    USE SIGNAL ;
    PORT
      LAYER M4 ;
      RECT 0.00000 27.88800 0.03600 27.91200 ;
    END
  END wdata[205]
  PIN wdata[206]
    DIRECTION INPUT ;
    USE SIGNAL ;
    PORT
      LAYER M4 ;
      RECT 0.00000 27.93600 0.03600 27.96000 ;
    END
  END wdata[206]
  PIN wdata[207]
    DIRECTION INPUT ;
    USE SIGNAL ;
    PORT
      LAYER M4 ;
      RECT 0.00000 27.98400 0.03600 28.00800 ;
    END
  END wdata[207]
  PIN wdata[208]
    DIRECTION INPUT ;
    USE SIGNAL ;
    PORT
      LAYER M4 ;
      RECT 0.00000 28.03200 0.03600 28.05600 ;
    END
  END wdata[208]
  PIN wdata[209]
    DIRECTION INPUT ;
    USE SIGNAL ;
    PORT
      LAYER M4 ;
      RECT 0.00000 28.08000 0.03600 28.10400 ;
    END
  END wdata[209]
  PIN wdata[210]
    DIRECTION INPUT ;
    USE SIGNAL ;
    PORT
      LAYER M4 ;
      RECT 0.00000 28.12800 0.03600 28.15200 ;
    END
  END wdata[210]
  PIN wdata[211]
    DIRECTION INPUT ;
    USE SIGNAL ;
    PORT
      LAYER M4 ;
      RECT 0.00000 28.17600 0.03600 28.20000 ;
    END
  END wdata[211]
  PIN wdata[212]
    DIRECTION INPUT ;
    USE SIGNAL ;
    PORT
      LAYER M4 ;
      RECT 0.00000 28.22400 0.03600 28.24800 ;
    END
  END wdata[212]
  PIN wdata[213]
    DIRECTION INPUT ;
    USE SIGNAL ;
    PORT
      LAYER M4 ;
      RECT 0.00000 28.27200 0.03600 28.29600 ;
    END
  END wdata[213]
  PIN wdata[214]
    DIRECTION INPUT ;
    USE SIGNAL ;
    PORT
      LAYER M4 ;
      RECT 0.00000 28.32000 0.03600 28.34400 ;
    END
  END wdata[214]
  PIN wdata[215]
    DIRECTION INPUT ;
    USE SIGNAL ;
    PORT
      LAYER M4 ;
      RECT 0.00000 28.36800 0.03600 28.39200 ;
    END
  END wdata[215]
  PIN wdata[216]
    DIRECTION INPUT ;
    USE SIGNAL ;
    PORT
      LAYER M4 ;
      RECT 0.00000 28.41600 0.03600 28.44000 ;
    END
  END wdata[216]
  PIN wdata[217]
    DIRECTION INPUT ;
    USE SIGNAL ;
    PORT
      LAYER M4 ;
      RECT 0.00000 28.46400 0.03600 28.48800 ;
    END
  END wdata[217]
  PIN wdata[218]
    DIRECTION INPUT ;
    USE SIGNAL ;
    PORT
      LAYER M4 ;
      RECT 0.00000 28.51200 0.03600 28.53600 ;
    END
  END wdata[218]
  PIN wdata[219]
    DIRECTION INPUT ;
    USE SIGNAL ;
    PORT
      LAYER M4 ;
      RECT 0.00000 28.56000 0.03600 28.58400 ;
    END
  END wdata[219]
  PIN wdata[220]
    DIRECTION INPUT ;
    USE SIGNAL ;
    PORT
      LAYER M4 ;
      RECT 0.00000 28.60800 0.03600 28.63200 ;
    END
  END wdata[220]
  PIN wdata[221]
    DIRECTION INPUT ;
    USE SIGNAL ;
    PORT
      LAYER M4 ;
      RECT 0.00000 28.65600 0.03600 28.68000 ;
    END
  END wdata[221]
  PIN wdata[222]
    DIRECTION INPUT ;
    USE SIGNAL ;
    PORT
      LAYER M4 ;
      RECT 0.00000 28.70400 0.03600 28.72800 ;
    END
  END wdata[222]
  PIN wdata[223]
    DIRECTION INPUT ;
    USE SIGNAL ;
    PORT
      LAYER M4 ;
      RECT 0.00000 28.75200 0.03600 28.77600 ;
    END
  END wdata[223]
  PIN wdata[224]
    DIRECTION INPUT ;
    USE SIGNAL ;
    PORT
      LAYER M4 ;
      RECT 0.00000 28.80000 0.03600 28.82400 ;
    END
  END wdata[224]
  PIN wdata[225]
    DIRECTION INPUT ;
    USE SIGNAL ;
    PORT
      LAYER M4 ;
      RECT 0.00000 28.84800 0.03600 28.87200 ;
    END
  END wdata[225]
  PIN wdata[226]
    DIRECTION INPUT ;
    USE SIGNAL ;
    PORT
      LAYER M4 ;
      RECT 0.00000 28.89600 0.03600 28.92000 ;
    END
  END wdata[226]
  PIN wdata[227]
    DIRECTION INPUT ;
    USE SIGNAL ;
    PORT
      LAYER M4 ;
      RECT 0.00000 28.94400 0.03600 28.96800 ;
    END
  END wdata[227]
  PIN wdata[228]
    DIRECTION INPUT ;
    USE SIGNAL ;
    PORT
      LAYER M4 ;
      RECT 0.00000 28.99200 0.03600 29.01600 ;
    END
  END wdata[228]
  PIN wdata[229]
    DIRECTION INPUT ;
    USE SIGNAL ;
    PORT
      LAYER M4 ;
      RECT 0.00000 29.04000 0.03600 29.06400 ;
    END
  END wdata[229]
  PIN wdata[230]
    DIRECTION INPUT ;
    USE SIGNAL ;
    PORT
      LAYER M4 ;
      RECT 0.00000 29.08800 0.03600 29.11200 ;
    END
  END wdata[230]
  PIN wdata[231]
    DIRECTION INPUT ;
    USE SIGNAL ;
    PORT
      LAYER M4 ;
      RECT 0.00000 29.13600 0.03600 29.16000 ;
    END
  END wdata[231]
  PIN wdata[232]
    DIRECTION INPUT ;
    USE SIGNAL ;
    PORT
      LAYER M4 ;
      RECT 0.00000 29.18400 0.03600 29.20800 ;
    END
  END wdata[232]
  PIN wdata[233]
    DIRECTION INPUT ;
    USE SIGNAL ;
    PORT
      LAYER M4 ;
      RECT 0.00000 29.23200 0.03600 29.25600 ;
    END
  END wdata[233]
  PIN wdata[234]
    DIRECTION INPUT ;
    USE SIGNAL ;
    PORT
      LAYER M4 ;
      RECT 0.00000 29.28000 0.03600 29.30400 ;
    END
  END wdata[234]
  PIN wdata[235]
    DIRECTION INPUT ;
    USE SIGNAL ;
    PORT
      LAYER M4 ;
      RECT 0.00000 29.32800 0.03600 29.35200 ;
    END
  END wdata[235]
  PIN wdata[236]
    DIRECTION INPUT ;
    USE SIGNAL ;
    PORT
      LAYER M4 ;
      RECT 0.00000 29.37600 0.03600 29.40000 ;
    END
  END wdata[236]
  PIN wdata[237]
    DIRECTION INPUT ;
    USE SIGNAL ;
    PORT
      LAYER M4 ;
      RECT 0.00000 29.42400 0.03600 29.44800 ;
    END
  END wdata[237]
  PIN wdata[238]
    DIRECTION INPUT ;
    USE SIGNAL ;
    PORT
      LAYER M4 ;
      RECT 0.00000 29.47200 0.03600 29.49600 ;
    END
  END wdata[238]
  PIN wdata[239]
    DIRECTION INPUT ;
    USE SIGNAL ;
    PORT
      LAYER M4 ;
      RECT 0.00000 29.52000 0.03600 29.54400 ;
    END
  END wdata[239]
  PIN wdata[240]
    DIRECTION INPUT ;
    USE SIGNAL ;
    PORT
      LAYER M4 ;
      RECT 0.00000 29.56800 0.03600 29.59200 ;
    END
  END wdata[240]
  PIN wdata[241]
    DIRECTION INPUT ;
    USE SIGNAL ;
    PORT
      LAYER M4 ;
      RECT 0.00000 29.61600 0.03600 29.64000 ;
    END
  END wdata[241]
  PIN wdata[242]
    DIRECTION INPUT ;
    USE SIGNAL ;
    PORT
      LAYER M4 ;
      RECT 0.00000 29.66400 0.03600 29.68800 ;
    END
  END wdata[242]
  PIN wdata[243]
    DIRECTION INPUT ;
    USE SIGNAL ;
    PORT
      LAYER M4 ;
      RECT 0.00000 29.71200 0.03600 29.73600 ;
    END
  END wdata[243]
  PIN wdata[244]
    DIRECTION INPUT ;
    USE SIGNAL ;
    PORT
      LAYER M4 ;
      RECT 0.00000 29.76000 0.03600 29.78400 ;
    END
  END wdata[244]
  PIN wdata[245]
    DIRECTION INPUT ;
    USE SIGNAL ;
    PORT
      LAYER M4 ;
      RECT 0.00000 29.80800 0.03600 29.83200 ;
    END
  END wdata[245]
  PIN wdata[246]
    DIRECTION INPUT ;
    USE SIGNAL ;
    PORT
      LAYER M4 ;
      RECT 0.00000 29.85600 0.03600 29.88000 ;
    END
  END wdata[246]
  PIN wdata[247]
    DIRECTION INPUT ;
    USE SIGNAL ;
    PORT
      LAYER M4 ;
      RECT 0.00000 29.90400 0.03600 29.92800 ;
    END
  END wdata[247]
  PIN wdata[248]
    DIRECTION INPUT ;
    USE SIGNAL ;
    PORT
      LAYER M4 ;
      RECT 0.00000 29.95200 0.03600 29.97600 ;
    END
  END wdata[248]
  PIN wdata[249]
    DIRECTION INPUT ;
    USE SIGNAL ;
    PORT
      LAYER M4 ;
      RECT 0.00000 30.00000 0.03600 30.02400 ;
    END
  END wdata[249]
  PIN wdata[250]
    DIRECTION INPUT ;
    USE SIGNAL ;
    PORT
      LAYER M4 ;
      RECT 0.00000 30.04800 0.03600 30.07200 ;
    END
  END wdata[250]
  PIN wdata[251]
    DIRECTION INPUT ;
    USE SIGNAL ;
    PORT
      LAYER M4 ;
      RECT 0.00000 30.09600 0.03600 30.12000 ;
    END
  END wdata[251]
  PIN wdata[252]
    DIRECTION INPUT ;
    USE SIGNAL ;
    PORT
      LAYER M4 ;
      RECT 0.00000 30.14400 0.03600 30.16800 ;
    END
  END wdata[252]
  PIN wdata[253]
    DIRECTION INPUT ;
    USE SIGNAL ;
    PORT
      LAYER M4 ;
      RECT 0.00000 30.19200 0.03600 30.21600 ;
    END
  END wdata[253]
  PIN wdata[254]
    DIRECTION INPUT ;
    USE SIGNAL ;
    PORT
      LAYER M4 ;
      RECT 0.00000 30.24000 0.03600 30.26400 ;
    END
  END wdata[254]
  PIN wdata[255]
    DIRECTION INPUT ;
    USE SIGNAL ;
    PORT
      LAYER M4 ;
      RECT 0.00000 30.28800 0.03600 30.31200 ;
    END
  END wdata[255]
  PIN waddr[0]
    DIRECTION INPUT ;
    USE SIGNAL ;
    PORT
      LAYER M4 ;
      RECT 0.00000 35.71200 0.03600 35.73600 ;
    END
  END waddr[0]
  PIN waddr[1]
    DIRECTION INPUT ;
    USE SIGNAL ;
    PORT
      LAYER M4 ;
      RECT 0.00000 35.76000 0.03600 35.78400 ;
    END
  END waddr[1]
  PIN waddr[2]
    DIRECTION INPUT ;
    USE SIGNAL ;
    PORT
      LAYER M4 ;
      RECT 0.00000 35.80800 0.03600 35.83200 ;
    END
  END waddr[2]
  PIN waddr[3]
    DIRECTION INPUT ;
    USE SIGNAL ;
    PORT
      LAYER M4 ;
      RECT 0.00000 35.85600 0.03600 35.88000 ;
    END
  END waddr[3]
  PIN waddr[4]
    DIRECTION INPUT ;
    USE SIGNAL ;
    PORT
      LAYER M4 ;
      RECT 0.00000 35.90400 0.03600 35.92800 ;
    END
  END waddr[4]
  PIN waddr[5]
    DIRECTION INPUT ;
    USE SIGNAL ;
    PORT
      LAYER M4 ;
      RECT 0.00000 35.95200 0.03600 35.97600 ;
    END
  END waddr[5]
  PIN waddr[6]
    DIRECTION INPUT ;
    USE SIGNAL ;
    PORT
      LAYER M4 ;
      RECT 0.00000 36.00000 0.03600 36.02400 ;
    END
  END waddr[6]
  PIN rb_data[0]
    DIRECTION OUTPUT ;
    USE SIGNAL ;
    PORT
      LAYER M4 ;
      RECT 0.00000 0.04800 0.03600 0.07200 ;
    END
  END rb_data[0]
  PIN rb_data[1]
    DIRECTION OUTPUT ;
    USE SIGNAL ;
    PORT
      LAYER M4 ;
      RECT 0.00000 0.09600 0.03600 0.12000 ;
    END
  END rb_data[1]
  PIN rb_data[2]
    DIRECTION OUTPUT ;
    USE SIGNAL ;
    PORT
      LAYER M4 ;
      RECT 0.00000 0.14400 0.03600 0.16800 ;
    END
  END rb_data[2]
  PIN rb_data[3]
    DIRECTION OUTPUT ;
    USE SIGNAL ;
    PORT
      LAYER M4 ;
      RECT 0.00000 0.19200 0.03600 0.21600 ;
    END
  END rb_data[3]
  PIN rb_data[4]
    DIRECTION OUTPUT ;
    USE SIGNAL ;
    PORT
      LAYER M4 ;
      RECT 0.00000 0.24000 0.03600 0.26400 ;
    END
  END rb_data[4]
  PIN rb_data[5]
    DIRECTION OUTPUT ;
    USE SIGNAL ;
    PORT
      LAYER M4 ;
      RECT 0.00000 0.28800 0.03600 0.31200 ;
    END
  END rb_data[5]
  PIN rb_data[6]
    DIRECTION OUTPUT ;
    USE SIGNAL ;
    PORT
      LAYER M4 ;
      RECT 0.00000 0.33600 0.03600 0.36000 ;
    END
  END rb_data[6]
  PIN rb_data[7]
    DIRECTION OUTPUT ;
    USE SIGNAL ;
    PORT
      LAYER M4 ;
      RECT 0.00000 0.38400 0.03600 0.40800 ;
    END
  END rb_data[7]
  PIN rb_data[8]
    DIRECTION OUTPUT ;
    USE SIGNAL ;
    PORT
      LAYER M4 ;
      RECT 0.00000 0.43200 0.03600 0.45600 ;
    END
  END rb_data[8]
  PIN rb_data[9]
    DIRECTION OUTPUT ;
    USE SIGNAL ;
    PORT
      LAYER M4 ;
      RECT 0.00000 0.48000 0.03600 0.50400 ;
    END
  END rb_data[9]
  PIN rb_data[10]
    DIRECTION OUTPUT ;
    USE SIGNAL ;
    PORT
      LAYER M4 ;
      RECT 0.00000 0.52800 0.03600 0.55200 ;
    END
  END rb_data[10]
  PIN rb_data[11]
    DIRECTION OUTPUT ;
    USE SIGNAL ;
    PORT
      LAYER M4 ;
      RECT 0.00000 0.57600 0.03600 0.60000 ;
    END
  END rb_data[11]
  PIN rb_data[12]
    DIRECTION OUTPUT ;
    USE SIGNAL ;
    PORT
      LAYER M4 ;
      RECT 0.00000 0.62400 0.03600 0.64800 ;
    END
  END rb_data[12]
  PIN rb_data[13]
    DIRECTION OUTPUT ;
    USE SIGNAL ;
    PORT
      LAYER M4 ;
      RECT 0.00000 0.67200 0.03600 0.69600 ;
    END
  END rb_data[13]
  PIN rb_data[14]
    DIRECTION OUTPUT ;
    USE SIGNAL ;
    PORT
      LAYER M4 ;
      RECT 0.00000 0.72000 0.03600 0.74400 ;
    END
  END rb_data[14]
  PIN rb_data[15]
    DIRECTION OUTPUT ;
    USE SIGNAL ;
    PORT
      LAYER M4 ;
      RECT 0.00000 0.76800 0.03600 0.79200 ;
    END
  END rb_data[15]
  PIN rb_data[16]
    DIRECTION OUTPUT ;
    USE SIGNAL ;
    PORT
      LAYER M4 ;
      RECT 0.00000 0.81600 0.03600 0.84000 ;
    END
  END rb_data[16]
  PIN rb_data[17]
    DIRECTION OUTPUT ;
    USE SIGNAL ;
    PORT
      LAYER M4 ;
      RECT 0.00000 0.86400 0.03600 0.88800 ;
    END
  END rb_data[17]
  PIN rb_data[18]
    DIRECTION OUTPUT ;
    USE SIGNAL ;
    PORT
      LAYER M4 ;
      RECT 0.00000 0.91200 0.03600 0.93600 ;
    END
  END rb_data[18]
  PIN rb_data[19]
    DIRECTION OUTPUT ;
    USE SIGNAL ;
    PORT
      LAYER M4 ;
      RECT 0.00000 0.96000 0.03600 0.98400 ;
    END
  END rb_data[19]
  PIN rb_data[20]
    DIRECTION OUTPUT ;
    USE SIGNAL ;
    PORT
      LAYER M4 ;
      RECT 0.00000 1.00800 0.03600 1.03200 ;
    END
  END rb_data[20]
  PIN rb_data[21]
    DIRECTION OUTPUT ;
    USE SIGNAL ;
    PORT
      LAYER M4 ;
      RECT 0.00000 1.05600 0.03600 1.08000 ;
    END
  END rb_data[21]
  PIN rb_data[22]
    DIRECTION OUTPUT ;
    USE SIGNAL ;
    PORT
      LAYER M4 ;
      RECT 0.00000 1.10400 0.03600 1.12800 ;
    END
  END rb_data[22]
  PIN rb_data[23]
    DIRECTION OUTPUT ;
    USE SIGNAL ;
    PORT
      LAYER M4 ;
      RECT 0.00000 1.15200 0.03600 1.17600 ;
    END
  END rb_data[23]
  PIN rb_data[24]
    DIRECTION OUTPUT ;
    USE SIGNAL ;
    PORT
      LAYER M4 ;
      RECT 0.00000 1.20000 0.03600 1.22400 ;
    END
  END rb_data[24]
  PIN rb_data[25]
    DIRECTION OUTPUT ;
    USE SIGNAL ;
    PORT
      LAYER M4 ;
      RECT 0.00000 1.24800 0.03600 1.27200 ;
    END
  END rb_data[25]
  PIN rb_data[26]
    DIRECTION OUTPUT ;
    USE SIGNAL ;
    PORT
      LAYER M4 ;
      RECT 0.00000 1.29600 0.03600 1.32000 ;
    END
  END rb_data[26]
  PIN rb_data[27]
    DIRECTION OUTPUT ;
    USE SIGNAL ;
    PORT
      LAYER M4 ;
      RECT 0.00000 1.34400 0.03600 1.36800 ;
    END
  END rb_data[27]
  PIN rb_data[28]
    DIRECTION OUTPUT ;
    USE SIGNAL ;
    PORT
      LAYER M4 ;
      RECT 0.00000 1.39200 0.03600 1.41600 ;
    END
  END rb_data[28]
  PIN rb_data[29]
    DIRECTION OUTPUT ;
    USE SIGNAL ;
    PORT
      LAYER M4 ;
      RECT 0.00000 1.44000 0.03600 1.46400 ;
    END
  END rb_data[29]
  PIN rb_data[30]
    DIRECTION OUTPUT ;
    USE SIGNAL ;
    PORT
      LAYER M4 ;
      RECT 0.00000 1.48800 0.03600 1.51200 ;
    END
  END rb_data[30]
  PIN rb_data[31]
    DIRECTION OUTPUT ;
    USE SIGNAL ;
    PORT
      LAYER M4 ;
      RECT 0.00000 1.53600 0.03600 1.56000 ;
    END
  END rb_data[31]
  PIN rb_data[32]
    DIRECTION OUTPUT ;
    USE SIGNAL ;
    PORT
      LAYER M4 ;
      RECT 0.00000 1.58400 0.03600 1.60800 ;
    END
  END rb_data[32]
  PIN rb_data[33]
    DIRECTION OUTPUT ;
    USE SIGNAL ;
    PORT
      LAYER M4 ;
      RECT 0.00000 1.63200 0.03600 1.65600 ;
    END
  END rb_data[33]
  PIN rb_data[34]
    DIRECTION OUTPUT ;
    USE SIGNAL ;
    PORT
      LAYER M4 ;
      RECT 0.00000 1.68000 0.03600 1.70400 ;
    END
  END rb_data[34]
  PIN rb_data[35]
    DIRECTION OUTPUT ;
    USE SIGNAL ;
    PORT
      LAYER M4 ;
      RECT 0.00000 1.72800 0.03600 1.75200 ;
    END
  END rb_data[35]
  PIN rb_data[36]
    DIRECTION OUTPUT ;
    USE SIGNAL ;
    PORT
      LAYER M4 ;
      RECT 0.00000 1.77600 0.03600 1.80000 ;
    END
  END rb_data[36]
  PIN rb_data[37]
    DIRECTION OUTPUT ;
    USE SIGNAL ;
    PORT
      LAYER M4 ;
      RECT 0.00000 1.82400 0.03600 1.84800 ;
    END
  END rb_data[37]
  PIN rb_data[38]
    DIRECTION OUTPUT ;
    USE SIGNAL ;
    PORT
      LAYER M4 ;
      RECT 0.00000 1.87200 0.03600 1.89600 ;
    END
  END rb_data[38]
  PIN rb_data[39]
    DIRECTION OUTPUT ;
    USE SIGNAL ;
    PORT
      LAYER M4 ;
      RECT 0.00000 1.92000 0.03600 1.94400 ;
    END
  END rb_data[39]
  PIN rb_data[40]
    DIRECTION OUTPUT ;
    USE SIGNAL ;
    PORT
      LAYER M4 ;
      RECT 0.00000 1.96800 0.03600 1.99200 ;
    END
  END rb_data[40]
  PIN rb_data[41]
    DIRECTION OUTPUT ;
    USE SIGNAL ;
    PORT
      LAYER M4 ;
      RECT 0.00000 2.01600 0.03600 2.04000 ;
    END
  END rb_data[41]
  PIN rb_data[42]
    DIRECTION OUTPUT ;
    USE SIGNAL ;
    PORT
      LAYER M4 ;
      RECT 0.00000 2.06400 0.03600 2.08800 ;
    END
  END rb_data[42]
  PIN rb_data[43]
    DIRECTION OUTPUT ;
    USE SIGNAL ;
    PORT
      LAYER M4 ;
      RECT 0.00000 2.11200 0.03600 2.13600 ;
    END
  END rb_data[43]
  PIN rb_data[44]
    DIRECTION OUTPUT ;
    USE SIGNAL ;
    PORT
      LAYER M4 ;
      RECT 0.00000 2.16000 0.03600 2.18400 ;
    END
  END rb_data[44]
  PIN rb_data[45]
    DIRECTION OUTPUT ;
    USE SIGNAL ;
    PORT
      LAYER M4 ;
      RECT 0.00000 2.20800 0.03600 2.23200 ;
    END
  END rb_data[45]
  PIN rb_data[46]
    DIRECTION OUTPUT ;
    USE SIGNAL ;
    PORT
      LAYER M4 ;
      RECT 0.00000 2.25600 0.03600 2.28000 ;
    END
  END rb_data[46]
  PIN rb_data[47]
    DIRECTION OUTPUT ;
    USE SIGNAL ;
    PORT
      LAYER M4 ;
      RECT 0.00000 2.30400 0.03600 2.32800 ;
    END
  END rb_data[47]
  PIN rb_data[48]
    DIRECTION OUTPUT ;
    USE SIGNAL ;
    PORT
      LAYER M4 ;
      RECT 0.00000 2.35200 0.03600 2.37600 ;
    END
  END rb_data[48]
  PIN rb_data[49]
    DIRECTION OUTPUT ;
    USE SIGNAL ;
    PORT
      LAYER M4 ;
      RECT 0.00000 2.40000 0.03600 2.42400 ;
    END
  END rb_data[49]
  PIN rb_data[50]
    DIRECTION OUTPUT ;
    USE SIGNAL ;
    PORT
      LAYER M4 ;
      RECT 0.00000 2.44800 0.03600 2.47200 ;
    END
  END rb_data[50]
  PIN rb_data[51]
    DIRECTION OUTPUT ;
    USE SIGNAL ;
    PORT
      LAYER M4 ;
      RECT 0.00000 2.49600 0.03600 2.52000 ;
    END
  END rb_data[51]
  PIN rb_data[52]
    DIRECTION OUTPUT ;
    USE SIGNAL ;
    PORT
      LAYER M4 ;
      RECT 0.00000 2.54400 0.03600 2.56800 ;
    END
  END rb_data[52]
  PIN rb_data[53]
    DIRECTION OUTPUT ;
    USE SIGNAL ;
    PORT
      LAYER M4 ;
      RECT 0.00000 2.59200 0.03600 2.61600 ;
    END
  END rb_data[53]
  PIN rb_data[54]
    DIRECTION OUTPUT ;
    USE SIGNAL ;
    PORT
      LAYER M4 ;
      RECT 0.00000 2.64000 0.03600 2.66400 ;
    END
  END rb_data[54]
  PIN rb_data[55]
    DIRECTION OUTPUT ;
    USE SIGNAL ;
    PORT
      LAYER M4 ;
      RECT 0.00000 2.68800 0.03600 2.71200 ;
    END
  END rb_data[55]
  PIN rb_data[56]
    DIRECTION OUTPUT ;
    USE SIGNAL ;
    PORT
      LAYER M4 ;
      RECT 0.00000 2.73600 0.03600 2.76000 ;
    END
  END rb_data[56]
  PIN rb_data[57]
    DIRECTION OUTPUT ;
    USE SIGNAL ;
    PORT
      LAYER M4 ;
      RECT 0.00000 2.78400 0.03600 2.80800 ;
    END
  END rb_data[57]
  PIN rb_data[58]
    DIRECTION OUTPUT ;
    USE SIGNAL ;
    PORT
      LAYER M4 ;
      RECT 0.00000 2.83200 0.03600 2.85600 ;
    END
  END rb_data[58]
  PIN rb_data[59]
    DIRECTION OUTPUT ;
    USE SIGNAL ;
    PORT
      LAYER M4 ;
      RECT 0.00000 2.88000 0.03600 2.90400 ;
    END
  END rb_data[59]
  PIN rb_data[60]
    DIRECTION OUTPUT ;
    USE SIGNAL ;
    PORT
      LAYER M4 ;
      RECT 0.00000 2.92800 0.03600 2.95200 ;
    END
  END rb_data[60]
  PIN rb_data[61]
    DIRECTION OUTPUT ;
    USE SIGNAL ;
    PORT
      LAYER M4 ;
      RECT 0.00000 2.97600 0.03600 3.00000 ;
    END
  END rb_data[61]
  PIN rb_data[62]
    DIRECTION OUTPUT ;
    USE SIGNAL ;
    PORT
      LAYER M4 ;
      RECT 0.00000 3.02400 0.03600 3.04800 ;
    END
  END rb_data[62]
  PIN rb_data[63]
    DIRECTION OUTPUT ;
    USE SIGNAL ;
    PORT
      LAYER M4 ;
      RECT 0.00000 3.07200 0.03600 3.09600 ;
    END
  END rb_data[63]
  PIN rb_data[64]
    DIRECTION OUTPUT ;
    USE SIGNAL ;
    PORT
      LAYER M4 ;
      RECT 0.00000 3.12000 0.03600 3.14400 ;
    END
  END rb_data[64]
  PIN rb_data[65]
    DIRECTION OUTPUT ;
    USE SIGNAL ;
    PORT
      LAYER M4 ;
      RECT 0.00000 3.16800 0.03600 3.19200 ;
    END
  END rb_data[65]
  PIN rb_data[66]
    DIRECTION OUTPUT ;
    USE SIGNAL ;
    PORT
      LAYER M4 ;
      RECT 0.00000 3.21600 0.03600 3.24000 ;
    END
  END rb_data[66]
  PIN rb_data[67]
    DIRECTION OUTPUT ;
    USE SIGNAL ;
    PORT
      LAYER M4 ;
      RECT 0.00000 3.26400 0.03600 3.28800 ;
    END
  END rb_data[67]
  PIN rb_data[68]
    DIRECTION OUTPUT ;
    USE SIGNAL ;
    PORT
      LAYER M4 ;
      RECT 0.00000 3.31200 0.03600 3.33600 ;
    END
  END rb_data[68]
  PIN rb_data[69]
    DIRECTION OUTPUT ;
    USE SIGNAL ;
    PORT
      LAYER M4 ;
      RECT 0.00000 3.36000 0.03600 3.38400 ;
    END
  END rb_data[69]
  PIN rb_data[70]
    DIRECTION OUTPUT ;
    USE SIGNAL ;
    PORT
      LAYER M4 ;
      RECT 0.00000 3.40800 0.03600 3.43200 ;
    END
  END rb_data[70]
  PIN rb_data[71]
    DIRECTION OUTPUT ;
    USE SIGNAL ;
    PORT
      LAYER M4 ;
      RECT 0.00000 3.45600 0.03600 3.48000 ;
    END
  END rb_data[71]
  PIN rb_data[72]
    DIRECTION OUTPUT ;
    USE SIGNAL ;
    PORT
      LAYER M4 ;
      RECT 0.00000 3.50400 0.03600 3.52800 ;
    END
  END rb_data[72]
  PIN rb_data[73]
    DIRECTION OUTPUT ;
    USE SIGNAL ;
    PORT
      LAYER M4 ;
      RECT 0.00000 3.55200 0.03600 3.57600 ;
    END
  END rb_data[73]
  PIN rb_data[74]
    DIRECTION OUTPUT ;
    USE SIGNAL ;
    PORT
      LAYER M4 ;
      RECT 0.00000 3.60000 0.03600 3.62400 ;
    END
  END rb_data[74]
  PIN rb_data[75]
    DIRECTION OUTPUT ;
    USE SIGNAL ;
    PORT
      LAYER M4 ;
      RECT 0.00000 3.64800 0.03600 3.67200 ;
    END
  END rb_data[75]
  PIN rb_data[76]
    DIRECTION OUTPUT ;
    USE SIGNAL ;
    PORT
      LAYER M4 ;
      RECT 0.00000 3.69600 0.03600 3.72000 ;
    END
  END rb_data[76]
  PIN rb_data[77]
    DIRECTION OUTPUT ;
    USE SIGNAL ;
    PORT
      LAYER M4 ;
      RECT 0.00000 3.74400 0.03600 3.76800 ;
    END
  END rb_data[77]
  PIN rb_data[78]
    DIRECTION OUTPUT ;
    USE SIGNAL ;
    PORT
      LAYER M4 ;
      RECT 0.00000 3.79200 0.03600 3.81600 ;
    END
  END rb_data[78]
  PIN rb_data[79]
    DIRECTION OUTPUT ;
    USE SIGNAL ;
    PORT
      LAYER M4 ;
      RECT 0.00000 3.84000 0.03600 3.86400 ;
    END
  END rb_data[79]
  PIN rb_data[80]
    DIRECTION OUTPUT ;
    USE SIGNAL ;
    PORT
      LAYER M4 ;
      RECT 0.00000 3.88800 0.03600 3.91200 ;
    END
  END rb_data[80]
  PIN rb_data[81]
    DIRECTION OUTPUT ;
    USE SIGNAL ;
    PORT
      LAYER M4 ;
      RECT 0.00000 3.93600 0.03600 3.96000 ;
    END
  END rb_data[81]
  PIN rb_data[82]
    DIRECTION OUTPUT ;
    USE SIGNAL ;
    PORT
      LAYER M4 ;
      RECT 0.00000 3.98400 0.03600 4.00800 ;
    END
  END rb_data[82]
  PIN rb_data[83]
    DIRECTION OUTPUT ;
    USE SIGNAL ;
    PORT
      LAYER M4 ;
      RECT 0.00000 4.03200 0.03600 4.05600 ;
    END
  END rb_data[83]
  PIN rb_data[84]
    DIRECTION OUTPUT ;
    USE SIGNAL ;
    PORT
      LAYER M4 ;
      RECT 0.00000 4.08000 0.03600 4.10400 ;
    END
  END rb_data[84]
  PIN rb_data[85]
    DIRECTION OUTPUT ;
    USE SIGNAL ;
    PORT
      LAYER M4 ;
      RECT 0.00000 4.12800 0.03600 4.15200 ;
    END
  END rb_data[85]
  PIN rb_data[86]
    DIRECTION OUTPUT ;
    USE SIGNAL ;
    PORT
      LAYER M4 ;
      RECT 0.00000 4.17600 0.03600 4.20000 ;
    END
  END rb_data[86]
  PIN rb_data[87]
    DIRECTION OUTPUT ;
    USE SIGNAL ;
    PORT
      LAYER M4 ;
      RECT 0.00000 4.22400 0.03600 4.24800 ;
    END
  END rb_data[87]
  PIN rb_data[88]
    DIRECTION OUTPUT ;
    USE SIGNAL ;
    PORT
      LAYER M4 ;
      RECT 0.00000 4.27200 0.03600 4.29600 ;
    END
  END rb_data[88]
  PIN rb_data[89]
    DIRECTION OUTPUT ;
    USE SIGNAL ;
    PORT
      LAYER M4 ;
      RECT 0.00000 4.32000 0.03600 4.34400 ;
    END
  END rb_data[89]
  PIN rb_data[90]
    DIRECTION OUTPUT ;
    USE SIGNAL ;
    PORT
      LAYER M4 ;
      RECT 0.00000 4.36800 0.03600 4.39200 ;
    END
  END rb_data[90]
  PIN rb_data[91]
    DIRECTION OUTPUT ;
    USE SIGNAL ;
    PORT
      LAYER M4 ;
      RECT 0.00000 4.41600 0.03600 4.44000 ;
    END
  END rb_data[91]
  PIN rb_data[92]
    DIRECTION OUTPUT ;
    USE SIGNAL ;
    PORT
      LAYER M4 ;
      RECT 0.00000 4.46400 0.03600 4.48800 ;
    END
  END rb_data[92]
  PIN rb_data[93]
    DIRECTION OUTPUT ;
    USE SIGNAL ;
    PORT
      LAYER M4 ;
      RECT 0.00000 4.51200 0.03600 4.53600 ;
    END
  END rb_data[93]
  PIN rb_data[94]
    DIRECTION OUTPUT ;
    USE SIGNAL ;
    PORT
      LAYER M4 ;
      RECT 0.00000 4.56000 0.03600 4.58400 ;
    END
  END rb_data[94]
  PIN rb_data[95]
    DIRECTION OUTPUT ;
    USE SIGNAL ;
    PORT
      LAYER M4 ;
      RECT 0.00000 4.60800 0.03600 4.63200 ;
    END
  END rb_data[95]
  PIN rb_data[96]
    DIRECTION OUTPUT ;
    USE SIGNAL ;
    PORT
      LAYER M4 ;
      RECT 0.00000 4.65600 0.03600 4.68000 ;
    END
  END rb_data[96]
  PIN rb_data[97]
    DIRECTION OUTPUT ;
    USE SIGNAL ;
    PORT
      LAYER M4 ;
      RECT 0.00000 4.70400 0.03600 4.72800 ;
    END
  END rb_data[97]
  PIN rb_data[98]
    DIRECTION OUTPUT ;
    USE SIGNAL ;
    PORT
      LAYER M4 ;
      RECT 0.00000 4.75200 0.03600 4.77600 ;
    END
  END rb_data[98]
  PIN rb_data[99]
    DIRECTION OUTPUT ;
    USE SIGNAL ;
    PORT
      LAYER M4 ;
      RECT 0.00000 4.80000 0.03600 4.82400 ;
    END
  END rb_data[99]
  PIN rb_data[100]
    DIRECTION OUTPUT ;
    USE SIGNAL ;
    PORT
      LAYER M4 ;
      RECT 0.00000 4.84800 0.03600 4.87200 ;
    END
  END rb_data[100]
  PIN rb_data[101]
    DIRECTION OUTPUT ;
    USE SIGNAL ;
    PORT
      LAYER M4 ;
      RECT 0.00000 4.89600 0.03600 4.92000 ;
    END
  END rb_data[101]
  PIN rb_data[102]
    DIRECTION OUTPUT ;
    USE SIGNAL ;
    PORT
      LAYER M4 ;
      RECT 0.00000 4.94400 0.03600 4.96800 ;
    END
  END rb_data[102]
  PIN rb_data[103]
    DIRECTION OUTPUT ;
    USE SIGNAL ;
    PORT
      LAYER M4 ;
      RECT 0.00000 4.99200 0.03600 5.01600 ;
    END
  END rb_data[103]
  PIN rb_data[104]
    DIRECTION OUTPUT ;
    USE SIGNAL ;
    PORT
      LAYER M4 ;
      RECT 0.00000 5.04000 0.03600 5.06400 ;
    END
  END rb_data[104]
  PIN rb_data[105]
    DIRECTION OUTPUT ;
    USE SIGNAL ;
    PORT
      LAYER M4 ;
      RECT 0.00000 5.08800 0.03600 5.11200 ;
    END
  END rb_data[105]
  PIN rb_data[106]
    DIRECTION OUTPUT ;
    USE SIGNAL ;
    PORT
      LAYER M4 ;
      RECT 0.00000 5.13600 0.03600 5.16000 ;
    END
  END rb_data[106]
  PIN rb_data[107]
    DIRECTION OUTPUT ;
    USE SIGNAL ;
    PORT
      LAYER M4 ;
      RECT 0.00000 5.18400 0.03600 5.20800 ;
    END
  END rb_data[107]
  PIN rb_data[108]
    DIRECTION OUTPUT ;
    USE SIGNAL ;
    PORT
      LAYER M4 ;
      RECT 0.00000 5.23200 0.03600 5.25600 ;
    END
  END rb_data[108]
  PIN rb_data[109]
    DIRECTION OUTPUT ;
    USE SIGNAL ;
    PORT
      LAYER M4 ;
      RECT 0.00000 5.28000 0.03600 5.30400 ;
    END
  END rb_data[109]
  PIN rb_data[110]
    DIRECTION OUTPUT ;
    USE SIGNAL ;
    PORT
      LAYER M4 ;
      RECT 0.00000 5.32800 0.03600 5.35200 ;
    END
  END rb_data[110]
  PIN rb_data[111]
    DIRECTION OUTPUT ;
    USE SIGNAL ;
    PORT
      LAYER M4 ;
      RECT 0.00000 5.37600 0.03600 5.40000 ;
    END
  END rb_data[111]
  PIN rb_data[112]
    DIRECTION OUTPUT ;
    USE SIGNAL ;
    PORT
      LAYER M4 ;
      RECT 0.00000 5.42400 0.03600 5.44800 ;
    END
  END rb_data[112]
  PIN rb_data[113]
    DIRECTION OUTPUT ;
    USE SIGNAL ;
    PORT
      LAYER M4 ;
      RECT 0.00000 5.47200 0.03600 5.49600 ;
    END
  END rb_data[113]
  PIN rb_data[114]
    DIRECTION OUTPUT ;
    USE SIGNAL ;
    PORT
      LAYER M4 ;
      RECT 0.00000 5.52000 0.03600 5.54400 ;
    END
  END rb_data[114]
  PIN rb_data[115]
    DIRECTION OUTPUT ;
    USE SIGNAL ;
    PORT
      LAYER M4 ;
      RECT 0.00000 5.56800 0.03600 5.59200 ;
    END
  END rb_data[115]
  PIN rb_data[116]
    DIRECTION OUTPUT ;
    USE SIGNAL ;
    PORT
      LAYER M4 ;
      RECT 0.00000 5.61600 0.03600 5.64000 ;
    END
  END rb_data[116]
  PIN rb_data[117]
    DIRECTION OUTPUT ;
    USE SIGNAL ;
    PORT
      LAYER M4 ;
      RECT 0.00000 5.66400 0.03600 5.68800 ;
    END
  END rb_data[117]
  PIN rb_data[118]
    DIRECTION OUTPUT ;
    USE SIGNAL ;
    PORT
      LAYER M4 ;
      RECT 0.00000 5.71200 0.03600 5.73600 ;
    END
  END rb_data[118]
  PIN rb_data[119]
    DIRECTION OUTPUT ;
    USE SIGNAL ;
    PORT
      LAYER M4 ;
      RECT 0.00000 5.76000 0.03600 5.78400 ;
    END
  END rb_data[119]
  PIN rb_data[120]
    DIRECTION OUTPUT ;
    USE SIGNAL ;
    PORT
      LAYER M4 ;
      RECT 0.00000 5.80800 0.03600 5.83200 ;
    END
  END rb_data[120]
  PIN rb_data[121]
    DIRECTION OUTPUT ;
    USE SIGNAL ;
    PORT
      LAYER M4 ;
      RECT 0.00000 5.85600 0.03600 5.88000 ;
    END
  END rb_data[121]
  PIN rb_data[122]
    DIRECTION OUTPUT ;
    USE SIGNAL ;
    PORT
      LAYER M4 ;
      RECT 0.00000 5.90400 0.03600 5.92800 ;
    END
  END rb_data[122]
  PIN rb_data[123]
    DIRECTION OUTPUT ;
    USE SIGNAL ;
    PORT
      LAYER M4 ;
      RECT 0.00000 5.95200 0.03600 5.97600 ;
    END
  END rb_data[123]
  PIN rb_data[124]
    DIRECTION OUTPUT ;
    USE SIGNAL ;
    PORT
      LAYER M4 ;
      RECT 0.00000 6.00000 0.03600 6.02400 ;
    END
  END rb_data[124]
  PIN rb_data[125]
    DIRECTION OUTPUT ;
    USE SIGNAL ;
    PORT
      LAYER M4 ;
      RECT 0.00000 6.04800 0.03600 6.07200 ;
    END
  END rb_data[125]
  PIN rb_data[126]
    DIRECTION OUTPUT ;
    USE SIGNAL ;
    PORT
      LAYER M4 ;
      RECT 0.00000 6.09600 0.03600 6.12000 ;
    END
  END rb_data[126]
  PIN rb_data[127]
    DIRECTION OUTPUT ;
    USE SIGNAL ;
    PORT
      LAYER M4 ;
      RECT 0.00000 6.14400 0.03600 6.16800 ;
    END
  END rb_data[127]
  PIN rb_data[128]
    DIRECTION OUTPUT ;
    USE SIGNAL ;
    PORT
      LAYER M4 ;
      RECT 0.00000 6.19200 0.03600 6.21600 ;
    END
  END rb_data[128]
  PIN rb_data[129]
    DIRECTION OUTPUT ;
    USE SIGNAL ;
    PORT
      LAYER M4 ;
      RECT 0.00000 6.24000 0.03600 6.26400 ;
    END
  END rb_data[129]
  PIN rb_data[130]
    DIRECTION OUTPUT ;
    USE SIGNAL ;
    PORT
      LAYER M4 ;
      RECT 0.00000 6.28800 0.03600 6.31200 ;
    END
  END rb_data[130]
  PIN rb_data[131]
    DIRECTION OUTPUT ;
    USE SIGNAL ;
    PORT
      LAYER M4 ;
      RECT 0.00000 6.33600 0.03600 6.36000 ;
    END
  END rb_data[131]
  PIN rb_data[132]
    DIRECTION OUTPUT ;
    USE SIGNAL ;
    PORT
      LAYER M4 ;
      RECT 0.00000 6.38400 0.03600 6.40800 ;
    END
  END rb_data[132]
  PIN rb_data[133]
    DIRECTION OUTPUT ;
    USE SIGNAL ;
    PORT
      LAYER M4 ;
      RECT 0.00000 6.43200 0.03600 6.45600 ;
    END
  END rb_data[133]
  PIN rb_data[134]
    DIRECTION OUTPUT ;
    USE SIGNAL ;
    PORT
      LAYER M4 ;
      RECT 0.00000 6.48000 0.03600 6.50400 ;
    END
  END rb_data[134]
  PIN rb_data[135]
    DIRECTION OUTPUT ;
    USE SIGNAL ;
    PORT
      LAYER M4 ;
      RECT 0.00000 6.52800 0.03600 6.55200 ;
    END
  END rb_data[135]
  PIN rb_data[136]
    DIRECTION OUTPUT ;
    USE SIGNAL ;
    PORT
      LAYER M4 ;
      RECT 0.00000 6.57600 0.03600 6.60000 ;
    END
  END rb_data[136]
  PIN rb_data[137]
    DIRECTION OUTPUT ;
    USE SIGNAL ;
    PORT
      LAYER M4 ;
      RECT 0.00000 6.62400 0.03600 6.64800 ;
    END
  END rb_data[137]
  PIN rb_data[138]
    DIRECTION OUTPUT ;
    USE SIGNAL ;
    PORT
      LAYER M4 ;
      RECT 0.00000 6.67200 0.03600 6.69600 ;
    END
  END rb_data[138]
  PIN rb_data[139]
    DIRECTION OUTPUT ;
    USE SIGNAL ;
    PORT
      LAYER M4 ;
      RECT 0.00000 6.72000 0.03600 6.74400 ;
    END
  END rb_data[139]
  PIN rb_data[140]
    DIRECTION OUTPUT ;
    USE SIGNAL ;
    PORT
      LAYER M4 ;
      RECT 0.00000 6.76800 0.03600 6.79200 ;
    END
  END rb_data[140]
  PIN rb_data[141]
    DIRECTION OUTPUT ;
    USE SIGNAL ;
    PORT
      LAYER M4 ;
      RECT 0.00000 6.81600 0.03600 6.84000 ;
    END
  END rb_data[141]
  PIN rb_data[142]
    DIRECTION OUTPUT ;
    USE SIGNAL ;
    PORT
      LAYER M4 ;
      RECT 0.00000 6.86400 0.03600 6.88800 ;
    END
  END rb_data[142]
  PIN rb_data[143]
    DIRECTION OUTPUT ;
    USE SIGNAL ;
    PORT
      LAYER M4 ;
      RECT 0.00000 6.91200 0.03600 6.93600 ;
    END
  END rb_data[143]
  PIN rb_data[144]
    DIRECTION OUTPUT ;
    USE SIGNAL ;
    PORT
      LAYER M4 ;
      RECT 0.00000 6.96000 0.03600 6.98400 ;
    END
  END rb_data[144]
  PIN rb_data[145]
    DIRECTION OUTPUT ;
    USE SIGNAL ;
    PORT
      LAYER M4 ;
      RECT 0.00000 7.00800 0.03600 7.03200 ;
    END
  END rb_data[145]
  PIN rb_data[146]
    DIRECTION OUTPUT ;
    USE SIGNAL ;
    PORT
      LAYER M4 ;
      RECT 0.00000 7.05600 0.03600 7.08000 ;
    END
  END rb_data[146]
  PIN rb_data[147]
    DIRECTION OUTPUT ;
    USE SIGNAL ;
    PORT
      LAYER M4 ;
      RECT 0.00000 7.10400 0.03600 7.12800 ;
    END
  END rb_data[147]
  PIN rb_data[148]
    DIRECTION OUTPUT ;
    USE SIGNAL ;
    PORT
      LAYER M4 ;
      RECT 0.00000 7.15200 0.03600 7.17600 ;
    END
  END rb_data[148]
  PIN rb_data[149]
    DIRECTION OUTPUT ;
    USE SIGNAL ;
    PORT
      LAYER M4 ;
      RECT 0.00000 7.20000 0.03600 7.22400 ;
    END
  END rb_data[149]
  PIN rb_data[150]
    DIRECTION OUTPUT ;
    USE SIGNAL ;
    PORT
      LAYER M4 ;
      RECT 0.00000 7.24800 0.03600 7.27200 ;
    END
  END rb_data[150]
  PIN rb_data[151]
    DIRECTION OUTPUT ;
    USE SIGNAL ;
    PORT
      LAYER M4 ;
      RECT 0.00000 7.29600 0.03600 7.32000 ;
    END
  END rb_data[151]
  PIN rb_data[152]
    DIRECTION OUTPUT ;
    USE SIGNAL ;
    PORT
      LAYER M4 ;
      RECT 0.00000 7.34400 0.03600 7.36800 ;
    END
  END rb_data[152]
  PIN rb_data[153]
    DIRECTION OUTPUT ;
    USE SIGNAL ;
    PORT
      LAYER M4 ;
      RECT 0.00000 7.39200 0.03600 7.41600 ;
    END
  END rb_data[153]
  PIN rb_data[154]
    DIRECTION OUTPUT ;
    USE SIGNAL ;
    PORT
      LAYER M4 ;
      RECT 0.00000 7.44000 0.03600 7.46400 ;
    END
  END rb_data[154]
  PIN rb_data[155]
    DIRECTION OUTPUT ;
    USE SIGNAL ;
    PORT
      LAYER M4 ;
      RECT 0.00000 7.48800 0.03600 7.51200 ;
    END
  END rb_data[155]
  PIN rb_data[156]
    DIRECTION OUTPUT ;
    USE SIGNAL ;
    PORT
      LAYER M4 ;
      RECT 0.00000 7.53600 0.03600 7.56000 ;
    END
  END rb_data[156]
  PIN rb_data[157]
    DIRECTION OUTPUT ;
    USE SIGNAL ;
    PORT
      LAYER M4 ;
      RECT 0.00000 7.58400 0.03600 7.60800 ;
    END
  END rb_data[157]
  PIN rb_data[158]
    DIRECTION OUTPUT ;
    USE SIGNAL ;
    PORT
      LAYER M4 ;
      RECT 0.00000 7.63200 0.03600 7.65600 ;
    END
  END rb_data[158]
  PIN rb_data[159]
    DIRECTION OUTPUT ;
    USE SIGNAL ;
    PORT
      LAYER M4 ;
      RECT 0.00000 7.68000 0.03600 7.70400 ;
    END
  END rb_data[159]
  PIN rb_data[160]
    DIRECTION OUTPUT ;
    USE SIGNAL ;
    PORT
      LAYER M4 ;
      RECT 0.00000 7.72800 0.03600 7.75200 ;
    END
  END rb_data[160]
  PIN rb_data[161]
    DIRECTION OUTPUT ;
    USE SIGNAL ;
    PORT
      LAYER M4 ;
      RECT 0.00000 7.77600 0.03600 7.80000 ;
    END
  END rb_data[161]
  PIN rb_data[162]
    DIRECTION OUTPUT ;
    USE SIGNAL ;
    PORT
      LAYER M4 ;
      RECT 0.00000 7.82400 0.03600 7.84800 ;
    END
  END rb_data[162]
  PIN rb_data[163]
    DIRECTION OUTPUT ;
    USE SIGNAL ;
    PORT
      LAYER M4 ;
      RECT 0.00000 7.87200 0.03600 7.89600 ;
    END
  END rb_data[163]
  PIN rb_data[164]
    DIRECTION OUTPUT ;
    USE SIGNAL ;
    PORT
      LAYER M4 ;
      RECT 0.00000 7.92000 0.03600 7.94400 ;
    END
  END rb_data[164]
  PIN rb_data[165]
    DIRECTION OUTPUT ;
    USE SIGNAL ;
    PORT
      LAYER M4 ;
      RECT 0.00000 7.96800 0.03600 7.99200 ;
    END
  END rb_data[165]
  PIN rb_data[166]
    DIRECTION OUTPUT ;
    USE SIGNAL ;
    PORT
      LAYER M4 ;
      RECT 0.00000 8.01600 0.03600 8.04000 ;
    END
  END rb_data[166]
  PIN rb_data[167]
    DIRECTION OUTPUT ;
    USE SIGNAL ;
    PORT
      LAYER M4 ;
      RECT 0.00000 8.06400 0.03600 8.08800 ;
    END
  END rb_data[167]
  PIN rb_data[168]
    DIRECTION OUTPUT ;
    USE SIGNAL ;
    PORT
      LAYER M4 ;
      RECT 0.00000 8.11200 0.03600 8.13600 ;
    END
  END rb_data[168]
  PIN rb_data[169]
    DIRECTION OUTPUT ;
    USE SIGNAL ;
    PORT
      LAYER M4 ;
      RECT 0.00000 8.16000 0.03600 8.18400 ;
    END
  END rb_data[169]
  PIN rb_data[170]
    DIRECTION OUTPUT ;
    USE SIGNAL ;
    PORT
      LAYER M4 ;
      RECT 0.00000 8.20800 0.03600 8.23200 ;
    END
  END rb_data[170]
  PIN rb_data[171]
    DIRECTION OUTPUT ;
    USE SIGNAL ;
    PORT
      LAYER M4 ;
      RECT 0.00000 8.25600 0.03600 8.28000 ;
    END
  END rb_data[171]
  PIN rb_data[172]
    DIRECTION OUTPUT ;
    USE SIGNAL ;
    PORT
      LAYER M4 ;
      RECT 0.00000 8.30400 0.03600 8.32800 ;
    END
  END rb_data[172]
  PIN rb_data[173]
    DIRECTION OUTPUT ;
    USE SIGNAL ;
    PORT
      LAYER M4 ;
      RECT 0.00000 8.35200 0.03600 8.37600 ;
    END
  END rb_data[173]
  PIN rb_data[174]
    DIRECTION OUTPUT ;
    USE SIGNAL ;
    PORT
      LAYER M4 ;
      RECT 0.00000 8.40000 0.03600 8.42400 ;
    END
  END rb_data[174]
  PIN rb_data[175]
    DIRECTION OUTPUT ;
    USE SIGNAL ;
    PORT
      LAYER M4 ;
      RECT 0.00000 8.44800 0.03600 8.47200 ;
    END
  END rb_data[175]
  PIN rb_data[176]
    DIRECTION OUTPUT ;
    USE SIGNAL ;
    PORT
      LAYER M4 ;
      RECT 0.00000 8.49600 0.03600 8.52000 ;
    END
  END rb_data[176]
  PIN rb_data[177]
    DIRECTION OUTPUT ;
    USE SIGNAL ;
    PORT
      LAYER M4 ;
      RECT 0.00000 8.54400 0.03600 8.56800 ;
    END
  END rb_data[177]
  PIN rb_data[178]
    DIRECTION OUTPUT ;
    USE SIGNAL ;
    PORT
      LAYER M4 ;
      RECT 0.00000 8.59200 0.03600 8.61600 ;
    END
  END rb_data[178]
  PIN rb_data[179]
    DIRECTION OUTPUT ;
    USE SIGNAL ;
    PORT
      LAYER M4 ;
      RECT 0.00000 8.64000 0.03600 8.66400 ;
    END
  END rb_data[179]
  PIN rb_data[180]
    DIRECTION OUTPUT ;
    USE SIGNAL ;
    PORT
      LAYER M4 ;
      RECT 0.00000 8.68800 0.03600 8.71200 ;
    END
  END rb_data[180]
  PIN rb_data[181]
    DIRECTION OUTPUT ;
    USE SIGNAL ;
    PORT
      LAYER M4 ;
      RECT 0.00000 8.73600 0.03600 8.76000 ;
    END
  END rb_data[181]
  PIN rb_data[182]
    DIRECTION OUTPUT ;
    USE SIGNAL ;
    PORT
      LAYER M4 ;
      RECT 0.00000 8.78400 0.03600 8.80800 ;
    END
  END rb_data[182]
  PIN rb_data[183]
    DIRECTION OUTPUT ;
    USE SIGNAL ;
    PORT
      LAYER M4 ;
      RECT 0.00000 8.83200 0.03600 8.85600 ;
    END
  END rb_data[183]
  PIN rb_data[184]
    DIRECTION OUTPUT ;
    USE SIGNAL ;
    PORT
      LAYER M4 ;
      RECT 0.00000 8.88000 0.03600 8.90400 ;
    END
  END rb_data[184]
  PIN rb_data[185]
    DIRECTION OUTPUT ;
    USE SIGNAL ;
    PORT
      LAYER M4 ;
      RECT 0.00000 8.92800 0.03600 8.95200 ;
    END
  END rb_data[185]
  PIN rb_data[186]
    DIRECTION OUTPUT ;
    USE SIGNAL ;
    PORT
      LAYER M4 ;
      RECT 0.00000 8.97600 0.03600 9.00000 ;
    END
  END rb_data[186]
  PIN rb_data[187]
    DIRECTION OUTPUT ;
    USE SIGNAL ;
    PORT
      LAYER M4 ;
      RECT 0.00000 9.02400 0.03600 9.04800 ;
    END
  END rb_data[187]
  PIN rb_data[188]
    DIRECTION OUTPUT ;
    USE SIGNAL ;
    PORT
      LAYER M4 ;
      RECT 0.00000 9.07200 0.03600 9.09600 ;
    END
  END rb_data[188]
  PIN rb_data[189]
    DIRECTION OUTPUT ;
    USE SIGNAL ;
    PORT
      LAYER M4 ;
      RECT 0.00000 9.12000 0.03600 9.14400 ;
    END
  END rb_data[189]
  PIN rb_data[190]
    DIRECTION OUTPUT ;
    USE SIGNAL ;
    PORT
      LAYER M4 ;
      RECT 0.00000 9.16800 0.03600 9.19200 ;
    END
  END rb_data[190]
  PIN rb_data[191]
    DIRECTION OUTPUT ;
    USE SIGNAL ;
    PORT
      LAYER M4 ;
      RECT 0.00000 9.21600 0.03600 9.24000 ;
    END
  END rb_data[191]
  PIN rb_data[192]
    DIRECTION OUTPUT ;
    USE SIGNAL ;
    PORT
      LAYER M4 ;
      RECT 0.00000 9.26400 0.03600 9.28800 ;
    END
  END rb_data[192]
  PIN rb_data[193]
    DIRECTION OUTPUT ;
    USE SIGNAL ;
    PORT
      LAYER M4 ;
      RECT 0.00000 9.31200 0.03600 9.33600 ;
    END
  END rb_data[193]
  PIN rb_data[194]
    DIRECTION OUTPUT ;
    USE SIGNAL ;
    PORT
      LAYER M4 ;
      RECT 0.00000 9.36000 0.03600 9.38400 ;
    END
  END rb_data[194]
  PIN rb_data[195]
    DIRECTION OUTPUT ;
    USE SIGNAL ;
    PORT
      LAYER M4 ;
      RECT 0.00000 9.40800 0.03600 9.43200 ;
    END
  END rb_data[195]
  PIN rb_data[196]
    DIRECTION OUTPUT ;
    USE SIGNAL ;
    PORT
      LAYER M4 ;
      RECT 0.00000 9.45600 0.03600 9.48000 ;
    END
  END rb_data[196]
  PIN rb_data[197]
    DIRECTION OUTPUT ;
    USE SIGNAL ;
    PORT
      LAYER M4 ;
      RECT 0.00000 9.50400 0.03600 9.52800 ;
    END
  END rb_data[197]
  PIN rb_data[198]
    DIRECTION OUTPUT ;
    USE SIGNAL ;
    PORT
      LAYER M4 ;
      RECT 0.00000 9.55200 0.03600 9.57600 ;
    END
  END rb_data[198]
  PIN rb_data[199]
    DIRECTION OUTPUT ;
    USE SIGNAL ;
    PORT
      LAYER M4 ;
      RECT 0.00000 9.60000 0.03600 9.62400 ;
    END
  END rb_data[199]
  PIN rb_data[200]
    DIRECTION OUTPUT ;
    USE SIGNAL ;
    PORT
      LAYER M4 ;
      RECT 0.00000 9.64800 0.03600 9.67200 ;
    END
  END rb_data[200]
  PIN rb_data[201]
    DIRECTION OUTPUT ;
    USE SIGNAL ;
    PORT
      LAYER M4 ;
      RECT 0.00000 9.69600 0.03600 9.72000 ;
    END
  END rb_data[201]
  PIN rb_data[202]
    DIRECTION OUTPUT ;
    USE SIGNAL ;
    PORT
      LAYER M4 ;
      RECT 0.00000 9.74400 0.03600 9.76800 ;
    END
  END rb_data[202]
  PIN rb_data[203]
    DIRECTION OUTPUT ;
    USE SIGNAL ;
    PORT
      LAYER M4 ;
      RECT 0.00000 9.79200 0.03600 9.81600 ;
    END
  END rb_data[203]
  PIN rb_data[204]
    DIRECTION OUTPUT ;
    USE SIGNAL ;
    PORT
      LAYER M4 ;
      RECT 0.00000 9.84000 0.03600 9.86400 ;
    END
  END rb_data[204]
  PIN rb_data[205]
    DIRECTION OUTPUT ;
    USE SIGNAL ;
    PORT
      LAYER M4 ;
      RECT 0.00000 9.88800 0.03600 9.91200 ;
    END
  END rb_data[205]
  PIN rb_data[206]
    DIRECTION OUTPUT ;
    USE SIGNAL ;
    PORT
      LAYER M4 ;
      RECT 0.00000 9.93600 0.03600 9.96000 ;
    END
  END rb_data[206]
  PIN rb_data[207]
    DIRECTION OUTPUT ;
    USE SIGNAL ;
    PORT
      LAYER M4 ;
      RECT 0.00000 9.98400 0.03600 10.00800 ;
    END
  END rb_data[207]
  PIN rb_data[208]
    DIRECTION OUTPUT ;
    USE SIGNAL ;
    PORT
      LAYER M4 ;
      RECT 0.00000 10.03200 0.03600 10.05600 ;
    END
  END rb_data[208]
  PIN rb_data[209]
    DIRECTION OUTPUT ;
    USE SIGNAL ;
    PORT
      LAYER M4 ;
      RECT 0.00000 10.08000 0.03600 10.10400 ;
    END
  END rb_data[209]
  PIN rb_data[210]
    DIRECTION OUTPUT ;
    USE SIGNAL ;
    PORT
      LAYER M4 ;
      RECT 0.00000 10.12800 0.03600 10.15200 ;
    END
  END rb_data[210]
  PIN rb_data[211]
    DIRECTION OUTPUT ;
    USE SIGNAL ;
    PORT
      LAYER M4 ;
      RECT 0.00000 10.17600 0.03600 10.20000 ;
    END
  END rb_data[211]
  PIN rb_data[212]
    DIRECTION OUTPUT ;
    USE SIGNAL ;
    PORT
      LAYER M4 ;
      RECT 0.00000 10.22400 0.03600 10.24800 ;
    END
  END rb_data[212]
  PIN rb_data[213]
    DIRECTION OUTPUT ;
    USE SIGNAL ;
    PORT
      LAYER M4 ;
      RECT 0.00000 10.27200 0.03600 10.29600 ;
    END
  END rb_data[213]
  PIN rb_data[214]
    DIRECTION OUTPUT ;
    USE SIGNAL ;
    PORT
      LAYER M4 ;
      RECT 0.00000 10.32000 0.03600 10.34400 ;
    END
  END rb_data[214]
  PIN rb_data[215]
    DIRECTION OUTPUT ;
    USE SIGNAL ;
    PORT
      LAYER M4 ;
      RECT 0.00000 10.36800 0.03600 10.39200 ;
    END
  END rb_data[215]
  PIN rb_data[216]
    DIRECTION OUTPUT ;
    USE SIGNAL ;
    PORT
      LAYER M4 ;
      RECT 0.00000 10.41600 0.03600 10.44000 ;
    END
  END rb_data[216]
  PIN rb_data[217]
    DIRECTION OUTPUT ;
    USE SIGNAL ;
    PORT
      LAYER M4 ;
      RECT 0.00000 10.46400 0.03600 10.48800 ;
    END
  END rb_data[217]
  PIN rb_data[218]
    DIRECTION OUTPUT ;
    USE SIGNAL ;
    PORT
      LAYER M4 ;
      RECT 0.00000 10.51200 0.03600 10.53600 ;
    END
  END rb_data[218]
  PIN rb_data[219]
    DIRECTION OUTPUT ;
    USE SIGNAL ;
    PORT
      LAYER M4 ;
      RECT 0.00000 10.56000 0.03600 10.58400 ;
    END
  END rb_data[219]
  PIN rb_data[220]
    DIRECTION OUTPUT ;
    USE SIGNAL ;
    PORT
      LAYER M4 ;
      RECT 0.00000 10.60800 0.03600 10.63200 ;
    END
  END rb_data[220]
  PIN rb_data[221]
    DIRECTION OUTPUT ;
    USE SIGNAL ;
    PORT
      LAYER M4 ;
      RECT 0.00000 10.65600 0.03600 10.68000 ;
    END
  END rb_data[221]
  PIN rb_data[222]
    DIRECTION OUTPUT ;
    USE SIGNAL ;
    PORT
      LAYER M4 ;
      RECT 0.00000 10.70400 0.03600 10.72800 ;
    END
  END rb_data[222]
  PIN rb_data[223]
    DIRECTION OUTPUT ;
    USE SIGNAL ;
    PORT
      LAYER M4 ;
      RECT 0.00000 10.75200 0.03600 10.77600 ;
    END
  END rb_data[223]
  PIN rb_data[224]
    DIRECTION OUTPUT ;
    USE SIGNAL ;
    PORT
      LAYER M4 ;
      RECT 0.00000 10.80000 0.03600 10.82400 ;
    END
  END rb_data[224]
  PIN rb_data[225]
    DIRECTION OUTPUT ;
    USE SIGNAL ;
    PORT
      LAYER M4 ;
      RECT 0.00000 10.84800 0.03600 10.87200 ;
    END
  END rb_data[225]
  PIN rb_data[226]
    DIRECTION OUTPUT ;
    USE SIGNAL ;
    PORT
      LAYER M4 ;
      RECT 0.00000 10.89600 0.03600 10.92000 ;
    END
  END rb_data[226]
  PIN rb_data[227]
    DIRECTION OUTPUT ;
    USE SIGNAL ;
    PORT
      LAYER M4 ;
      RECT 0.00000 10.94400 0.03600 10.96800 ;
    END
  END rb_data[227]
  PIN rb_data[228]
    DIRECTION OUTPUT ;
    USE SIGNAL ;
    PORT
      LAYER M4 ;
      RECT 0.00000 10.99200 0.03600 11.01600 ;
    END
  END rb_data[228]
  PIN rb_data[229]
    DIRECTION OUTPUT ;
    USE SIGNAL ;
    PORT
      LAYER M4 ;
      RECT 0.00000 11.04000 0.03600 11.06400 ;
    END
  END rb_data[229]
  PIN rb_data[230]
    DIRECTION OUTPUT ;
    USE SIGNAL ;
    PORT
      LAYER M4 ;
      RECT 0.00000 11.08800 0.03600 11.11200 ;
    END
  END rb_data[230]
  PIN rb_data[231]
    DIRECTION OUTPUT ;
    USE SIGNAL ;
    PORT
      LAYER M4 ;
      RECT 0.00000 11.13600 0.03600 11.16000 ;
    END
  END rb_data[231]
  PIN rb_data[232]
    DIRECTION OUTPUT ;
    USE SIGNAL ;
    PORT
      LAYER M4 ;
      RECT 0.00000 11.18400 0.03600 11.20800 ;
    END
  END rb_data[232]
  PIN rb_data[233]
    DIRECTION OUTPUT ;
    USE SIGNAL ;
    PORT
      LAYER M4 ;
      RECT 0.00000 11.23200 0.03600 11.25600 ;
    END
  END rb_data[233]
  PIN rb_data[234]
    DIRECTION OUTPUT ;
    USE SIGNAL ;
    PORT
      LAYER M4 ;
      RECT 0.00000 11.28000 0.03600 11.30400 ;
    END
  END rb_data[234]
  PIN rb_data[235]
    DIRECTION OUTPUT ;
    USE SIGNAL ;
    PORT
      LAYER M4 ;
      RECT 0.00000 11.32800 0.03600 11.35200 ;
    END
  END rb_data[235]
  PIN rb_data[236]
    DIRECTION OUTPUT ;
    USE SIGNAL ;
    PORT
      LAYER M4 ;
      RECT 0.00000 11.37600 0.03600 11.40000 ;
    END
  END rb_data[236]
  PIN rb_data[237]
    DIRECTION OUTPUT ;
    USE SIGNAL ;
    PORT
      LAYER M4 ;
      RECT 0.00000 11.42400 0.03600 11.44800 ;
    END
  END rb_data[237]
  PIN rb_data[238]
    DIRECTION OUTPUT ;
    USE SIGNAL ;
    PORT
      LAYER M4 ;
      RECT 0.00000 11.47200 0.03600 11.49600 ;
    END
  END rb_data[238]
  PIN rb_data[239]
    DIRECTION OUTPUT ;
    USE SIGNAL ;
    PORT
      LAYER M4 ;
      RECT 0.00000 11.52000 0.03600 11.54400 ;
    END
  END rb_data[239]
  PIN rb_data[240]
    DIRECTION OUTPUT ;
    USE SIGNAL ;
    PORT
      LAYER M4 ;
      RECT 0.00000 11.56800 0.03600 11.59200 ;
    END
  END rb_data[240]
  PIN rb_data[241]
    DIRECTION OUTPUT ;
    USE SIGNAL ;
    PORT
      LAYER M4 ;
      RECT 0.00000 11.61600 0.03600 11.64000 ;
    END
  END rb_data[241]
  PIN rb_data[242]
    DIRECTION OUTPUT ;
    USE SIGNAL ;
    PORT
      LAYER M4 ;
      RECT 0.00000 11.66400 0.03600 11.68800 ;
    END
  END rb_data[242]
  PIN rb_data[243]
    DIRECTION OUTPUT ;
    USE SIGNAL ;
    PORT
      LAYER M4 ;
      RECT 0.00000 11.71200 0.03600 11.73600 ;
    END
  END rb_data[243]
  PIN rb_data[244]
    DIRECTION OUTPUT ;
    USE SIGNAL ;
    PORT
      LAYER M4 ;
      RECT 0.00000 11.76000 0.03600 11.78400 ;
    END
  END rb_data[244]
  PIN rb_data[245]
    DIRECTION OUTPUT ;
    USE SIGNAL ;
    PORT
      LAYER M4 ;
      RECT 0.00000 11.80800 0.03600 11.83200 ;
    END
  END rb_data[245]
  PIN rb_data[246]
    DIRECTION OUTPUT ;
    USE SIGNAL ;
    PORT
      LAYER M4 ;
      RECT 0.00000 11.85600 0.03600 11.88000 ;
    END
  END rb_data[246]
  PIN rb_data[247]
    DIRECTION OUTPUT ;
    USE SIGNAL ;
    PORT
      LAYER M4 ;
      RECT 0.00000 11.90400 0.03600 11.92800 ;
    END
  END rb_data[247]
  PIN rb_data[248]
    DIRECTION OUTPUT ;
    USE SIGNAL ;
    PORT
      LAYER M4 ;
      RECT 0.00000 11.95200 0.03600 11.97600 ;
    END
  END rb_data[248]
  PIN rb_data[249]
    DIRECTION OUTPUT ;
    USE SIGNAL ;
    PORT
      LAYER M4 ;
      RECT 0.00000 12.00000 0.03600 12.02400 ;
    END
  END rb_data[249]
  PIN rb_data[250]
    DIRECTION OUTPUT ;
    USE SIGNAL ;
    PORT
      LAYER M4 ;
      RECT 0.00000 12.04800 0.03600 12.07200 ;
    END
  END rb_data[250]
  PIN rb_data[251]
    DIRECTION OUTPUT ;
    USE SIGNAL ;
    PORT
      LAYER M4 ;
      RECT 0.00000 12.09600 0.03600 12.12000 ;
    END
  END rb_data[251]
  PIN rb_data[252]
    DIRECTION OUTPUT ;
    USE SIGNAL ;
    PORT
      LAYER M4 ;
      RECT 0.00000 12.14400 0.03600 12.16800 ;
    END
  END rb_data[252]
  PIN rb_data[253]
    DIRECTION OUTPUT ;
    USE SIGNAL ;
    PORT
      LAYER M4 ;
      RECT 0.00000 12.19200 0.03600 12.21600 ;
    END
  END rb_data[253]
  PIN rb_data[254]
    DIRECTION OUTPUT ;
    USE SIGNAL ;
    PORT
      LAYER M4 ;
      RECT 0.00000 12.24000 0.03600 12.26400 ;
    END
  END rb_data[254]
  PIN rb_data[255]
    DIRECTION OUTPUT ;
    USE SIGNAL ;
    PORT
      LAYER M4 ;
      RECT 0.00000 12.28800 0.03600 12.31200 ;
    END
  END rb_data[255]
  PIN rb_addr[0]
    DIRECTION INPUT ;
    USE SIGNAL ;
    PORT
      LAYER M4 ;
      RECT 0.00000 36.04800 0.03600 36.07200 ;
    END
  END rb_addr[0]
  PIN rb_addr[1]
    DIRECTION INPUT ;
    USE SIGNAL ;
    PORT
      LAYER M4 ;
      RECT 0.00000 36.09600 0.03600 36.12000 ;
    END
  END rb_addr[1]
  PIN rb_addr[2]
    DIRECTION INPUT ;
    USE SIGNAL ;
    PORT
      LAYER M4 ;
      RECT 0.00000 36.14400 0.03600 36.16800 ;
    END
  END rb_addr[2]
  PIN rb_addr[3]
    DIRECTION INPUT ;
    USE SIGNAL ;
    PORT
      LAYER M4 ;
      RECT 0.00000 36.19200 0.03600 36.21600 ;
    END
  END rb_addr[3]
  PIN rb_addr[4]
    DIRECTION INPUT ;
    USE SIGNAL ;
    PORT
      LAYER M4 ;
      RECT 0.00000 36.24000 0.03600 36.26400 ;
    END
  END rb_addr[4]
  PIN rb_addr[5]
    DIRECTION INPUT ;
    USE SIGNAL ;
    PORT
      LAYER M4 ;
      RECT 0.00000 36.28800 0.03600 36.31200 ;
    END
  END rb_addr[5]
  PIN rb_addr[6]
    DIRECTION INPUT ;
    USE SIGNAL ;
    PORT
      LAYER M4 ;
      RECT 0.00000 36.33600 0.03600 36.36000 ;
    END
  END rb_addr[6]
  PIN we[0]
    DIRECTION INPUT ;
    USE SIGNAL ;
    PORT
      LAYER M4 ;
      RECT 0.00000 41.80800 0.03600 41.83200 ;
    END
  END we[0]
  PIN we[1]
    DIRECTION INPUT ;
    USE SIGNAL ;
    PORT
      LAYER M4 ;
      RECT 0.00000 41.85600 0.03600 41.88000 ;
    END
  END we[1]
  PIN clk
    DIRECTION INPUT ;
    USE SIGNAL ;
    PORT
      LAYER M4 ;
      RECT 0.00000 41.76000 0.03600 41.78400 ;
    END
  END clk
  PIN rb_en
    DIRECTION INPUT ;
    USE SIGNAL ;
    PORT
      LAYER M4 ;
      RECT 0.00000 41.90400 0.03600 41.92800 ;
    END
  END rb_en
  PIN rb_addr_q[0]
    DIRECTION OUTPUT ;
    USE SIGNAL ;
    PORT
      LAYER M4 ;
      RECT 0.00000 12.33600 0.03600 12.36000 ;
    END
  END rb_addr_q[0]
  PIN rb_addr_q[1]
    DIRECTION OUTPUT ;
    USE SIGNAL ;
    PORT
      LAYER M4 ;
      RECT 0.00000 12.38400 0.03600 12.40800 ;
    END
  END rb_addr_q[1]
  PIN rb_addr_q[2]
    DIRECTION OUTPUT ;
    USE SIGNAL ;
    PORT
      LAYER M4 ;
      RECT 0.00000 12.43200 0.03600 12.45600 ;
    END
  END rb_addr_q[2]
  PIN rb_addr_q[3]
    DIRECTION OUTPUT ;
    USE SIGNAL ;
    PORT
      LAYER M4 ;
      RECT 0.00000 12.48000 0.03600 12.50400 ;
    END
  END rb_addr_q[3]
  PIN rb_addr_q[4]
    DIRECTION OUTPUT ;
    USE SIGNAL ;
    PORT
      LAYER M4 ;
      RECT 0.00000 12.52800 0.03600 12.55200 ;
    END
  END rb_addr_q[4]
  PIN rb_addr_q[5]
    DIRECTION OUTPUT ;
    USE SIGNAL ;
    PORT
      LAYER M4 ;
      RECT 0.00000 12.57600 0.03600 12.60000 ;
    END
  END rb_addr_q[5]
  PIN rb_addr_q[6]
    DIRECTION OUTPUT ;
    USE SIGNAL ;
    PORT
      LAYER M4 ;
      RECT 0.00000 12.62400 0.03600 12.64800 ;
    END
  END rb_addr_q[6]
  PIN VDD
    DIRECTION INOUT ;
    USE POWER ;
    PORT
      LAYER M4 ;
      RECT 0.09600 0.38400 33.15400 0.48000 ;
      RECT 0.09600 1.15200 33.15400 1.24800 ;
      RECT 0.09600 1.92000 33.15400 2.01600 ;
      RECT 0.09600 2.68800 33.15400 2.78400 ;
      RECT 0.09600 3.45600 33.15400 3.55200 ;
      RECT 0.09600 4.22400 33.15400 4.32000 ;
      RECT 0.09600 4.99200 33.15400 5.08800 ;
      RECT 0.09600 5.76000 33.15400 5.85600 ;
      RECT 0.09600 6.52800 33.15400 6.62400 ;
      RECT 0.09600 7.29600 33.15400 7.39200 ;
      RECT 0.09600 8.06400 33.15400 8.16000 ;
      RECT 0.09600 8.83200 33.15400 8.92800 ;
      RECT 0.09600 9.60000 33.15400 9.69600 ;
      RECT 0.09600 10.36800 33.15400 10.46400 ;
      RECT 0.09600 11.13600 33.15400 11.23200 ;
      RECT 0.09600 11.90400 33.15400 12.00000 ;
      RECT 0.09600 12.67200 33.15400 12.76800 ;
      RECT 0.09600 13.44000 33.15400 13.53600 ;
      RECT 0.09600 14.20800 33.15400 14.30400 ;
      RECT 0.09600 14.97600 33.15400 15.07200 ;
      RECT 0.09600 15.74400 33.15400 15.84000 ;
      RECT 0.09600 16.51200 33.15400 16.60800 ;
      RECT 0.09600 17.28000 33.15400 17.37600 ;
      RECT 0.09600 18.04800 33.15400 18.14400 ;
      RECT 0.09600 18.81600 33.15400 18.91200 ;
      RECT 0.09600 19.58400 33.15400 19.68000 ;
      RECT 0.09600 20.35200 33.15400 20.44800 ;
      RECT 0.09600 21.12000 33.15400 21.21600 ;
      RECT 0.09600 21.88800 33.15400 21.98400 ;
      RECT 0.09600 22.65600 33.15400 22.75200 ;
      RECT 0.09600 23.42400 33.15400 23.52000 ;
      RECT 0.09600 24.19200 33.15400 24.28800 ;
      RECT 0.09600 24.96000 33.15400 25.05600 ;
      RECT 0.09600 25.72800 33.15400 25.82400 ;
      RECT 0.09600 26.49600 33.15400 26.59200 ;
      RECT 0.09600 27.26400 33.15400 27.36000 ;
      RECT 0.09600 28.03200 33.15400 28.12800 ;
      RECT 0.09600 28.80000 33.15400 28.89600 ;
      RECT 0.09600 29.56800 33.15400 29.66400 ;
      RECT 0.09600 30.33600 33.15400 30.43200 ;
      RECT 0.09600 31.10400 33.15400 31.20000 ;
      RECT 0.09600 31.87200 33.15400 31.96800 ;
      RECT 0.09600 32.64000 33.15400 32.73600 ;
      RECT 0.09600 33.40800 33.15400 33.50400 ;
      RECT 0.09600 34.17600 33.15400 34.27200 ;
      RECT 0.09600 34.94400 33.15400 35.04000 ;
      RECT 0.09600 35.71200 33.15400 35.80800 ;
      RECT 0.09600 36.48000 33.15400 36.57600 ;
      RECT 0.09600 37.24800 33.15400 37.34400 ;
      RECT 0.09600 38.01600 33.15400 38.11200 ;
      RECT 0.09600 38.78400 33.15400 38.88000 ;
      RECT 0.09600 39.55200 33.15400 39.64800 ;
      RECT 0.09600 40.32000 33.15400 40.41600 ;
      RECT 0.09600 41.08800 33.15400 41.18400 ;
      RECT 0.09600 41.85600 33.15400 41.95200 ;
    END
  END VDD
  PIN VSS
    DIRECTION INOUT ;
    USE GROUND ;
    PORT
      LAYER M4 ;
      RECT 0.09600 0.00000 33.15400 0.09600 ;
      RECT 0.09600 0.76800 33.15400 0.86400 ;
      RECT 0.09600 1.53600 33.15400 1.63200 ;
      RECT 0.09600 2.30400 33.15400 2.40000 ;
      RECT 0.09600 3.07200 33.15400 3.16800 ;
      RECT 0.09600 3.84000 33.15400 3.93600 ;
      RECT 0.09600 4.60800 33.15400 4.70400 ;
      RECT 0.09600 5.37600 33.15400 5.47200 ;
      RECT 0.09600 6.14400 33.15400 6.24000 ;
      RECT 0.09600 6.91200 33.15400 7.00800 ;
      RECT 0.09600 7.68000 33.15400 7.77600 ;
      RECT 0.09600 8.44800 33.15400 8.54400 ;
      RECT 0.09600 9.21600 33.15400 9.31200 ;
      RECT 0.09600 9.98400 33.15400 10.08000 ;
      RECT 0.09600 10.75200 33.15400 10.84800 ;
      RECT 0.09600 11.52000 33.15400 11.61600 ;
      RECT 0.09600 12.28800 33.15400 12.38400 ;
      RECT 0.09600 13.05600 33.15400 13.15200 ;
      RECT 0.09600 13.82400 33.15400 13.92000 ;
      RECT 0.09600 14.59200 33.15400 14.68800 ;
      RECT 0.09600 15.36000 33.15400 15.45600 ;
      RECT 0.09600 16.12800 33.15400 16.22400 ;
      RECT 0.09600 16.89600 33.15400 16.99200 ;
      RECT 0.09600 17.66400 33.15400 17.76000 ;
      RECT 0.09600 18.43200 33.15400 18.52800 ;
      RECT 0.09600 19.20000 33.15400 19.29600 ;
      RECT 0.09600 19.96800 33.15400 20.06400 ;
      RECT 0.09600 20.73600 33.15400 20.83200 ;
      RECT 0.09600 21.50400 33.15400 21.60000 ;
      RECT 0.09600 22.27200 33.15400 22.36800 ;
      RECT 0.09600 23.04000 33.15400 23.13600 ;
      RECT 0.09600 23.80800 33.15400 23.90400 ;
      RECT 0.09600 24.57600 33.15400 24.67200 ;
      RECT 0.09600 25.34400 33.15400 25.44000 ;
      RECT 0.09600 26.11200 33.15400 26.20800 ;
      RECT 0.09600 26.88000 33.15400 26.97600 ;
      RECT 0.09600 27.64800 33.15400 27.74400 ;
      RECT 0.09600 28.41600 33.15400 28.51200 ;
      RECT 0.09600 29.18400 33.15400 29.28000 ;
      RECT 0.09600 29.95200 33.15400 30.04800 ;
      RECT 0.09600 30.72000 33.15400 30.81600 ;
      RECT 0.09600 31.48800 33.15400 31.58400 ;
      RECT 0.09600 32.25600 33.15400 32.35200 ;
      RECT 0.09600 33.02400 33.15400 33.12000 ;
      RECT 0.09600 33.79200 33.15400 33.88800 ;
      RECT 0.09600 34.56000 33.15400 34.65600 ;
      RECT 0.09600 35.32800 33.15400 35.42400 ;
      RECT 0.09600 36.09600 33.15400 36.19200 ;
      RECT 0.09600 36.86400 33.15400 36.96000 ;
      RECT 0.09600 37.63200 33.15400 37.72800 ;
      RECT 0.09600 38.40000 33.15400 38.49600 ;
      RECT 0.09600 39.16800 33.15400 39.26400 ;
      RECT 0.09600 39.93600 33.15400 40.03200 ;
      RECT 0.09600 40.70400 33.15400 40.80000 ;
      RECT 0.09600 41.47200 33.15400 41.56800 ;
    END
  END VSS
  OBS
    LAYER M1 ;
    RECT 0 0 33.25000 42.00000 ;
    LAYER M2 ;
    RECT 0 0 33.25000 42.00000 ;
    LAYER M3 ;
    RECT 0 0 33.25000 42.00000 ;
    LAYER M4 ;
    RECT 0 0 33.25000 42.00000 ;
  END
END fakeram7_128x256_g2_1w1r

END LIBRARY
